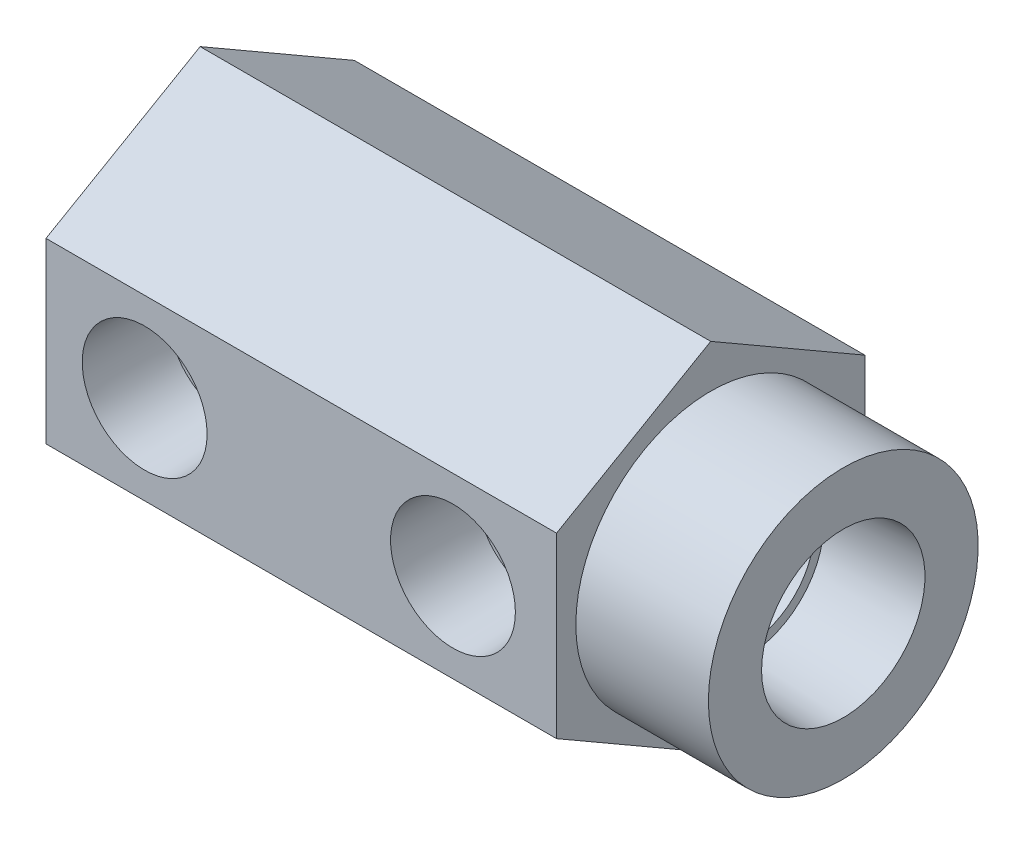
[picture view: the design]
ISO-10303-21;
HEADER;
FILE_DESCRIPTION(('STEP AP214'),'2;1');
FILE_NAME('part.step','',(''),(''),'','','');
FILE_SCHEMA(('AUTOMOTIVE_DESIGN { 1 0 10303 214 1 1 1 1 }'));
ENDSEC;
DATA;
#1=APPLICATION_CONTEXT('core data for automotive mechanical design processes');
#2=APPLICATION_PROTOCOL_DEFINITION('international standard','automotive_design',2000,#1);
#3=PRODUCT_CONTEXT('',#1,'mechanical');
#4=PRODUCT('Part','Part','',(#3));
#5=PRODUCT_RELATED_PRODUCT_CATEGORY('part','',(#4));
#6=PRODUCT_DEFINITION_FORMATION('','',#4);
#7=PRODUCT_DEFINITION_CONTEXT('part definition',#1,'design');
#8=PRODUCT_DEFINITION('design','',#6,#7);
#9=PRODUCT_DEFINITION_SHAPE('','',#8);
#10=(LENGTH_UNIT() NAMED_UNIT(*) SI_UNIT(.MILLI.,.METRE.));
#11=(NAMED_UNIT(*) PLANE_ANGLE_UNIT() SI_UNIT($,.RADIAN.));
#12=(NAMED_UNIT(*) SI_UNIT($,.STERADIAN.) SOLID_ANGLE_UNIT());
#13=UNCERTAINTY_MEASURE_WITH_UNIT(LENGTH_MEASURE(1.E-05),#10,'distance_accuracy_value','');
#14=(GEOMETRIC_REPRESENTATION_CONTEXT(3) GLOBAL_UNCERTAINTY_ASSIGNED_CONTEXT((#13)) GLOBAL_UNIT_ASSIGNED_CONTEXT((#10,
#11,#12)) REPRESENTATION_CONTEXT('',''));
#15=CARTESIAN_POINT('',(0.,0.,0.));
#16=DIRECTION('',(0.,0.,1.));
#17=DIRECTION('',(1.,0.,0.));
#18=AXIS2_PLACEMENT_3D('',#15,#16,#17);
#19=CARTESIAN_POINT('',(52.9844,0.,0.));
#20=DIRECTION('',(1.,0.,0.));
#21=DIRECTION('',(0.,0.,-1.));
#22=AXIS2_PLACEMENT_3D('',#19,#20,#21);
#23=CYLINDRICAL_SURFACE('',#22,3.96875);
#24=CARTESIAN_POINT('',(16.4084,0.,0.));
#25=DIRECTION('',(1.,0.,0.));
#26=DIRECTION('',(0.,0.,-1.));
#27=AXIS2_PLACEMENT_3D('',#24,#25,#26);
#28=CIRCLE('',#27,3.96874999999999);
#29=CARTESIAN_POINT('',(16.4084,0.,-3.96874999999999));
#30=VERTEX_POINT('',#29);
#31=EDGE_CURVE('E159',#30,#30,#28,.T.);
#32=ORIENTED_EDGE('',*,*,#31,.F.);
#33=EDGE_LOOP('',(#32));
#34=FACE_BOUND('',#33,.T.);
#35=CARTESIAN_POINT('',(27.5844,0.,0.));
#36=DIRECTION('',(1.,0.,0.));
#37=DIRECTION('',(0.,0.,-1.));
#38=AXIS2_PLACEMENT_3D('',#35,#36,#37);
#39=CIRCLE('',#38,3.96875);
#40=CARTESIAN_POINT('',(27.5844,0.,-3.96875));
#41=VERTEX_POINT('',#40);
#42=EDGE_CURVE('E38',#41,#41,#39,.F.);
#43=ORIENTED_EDGE('',*,*,#42,.F.);
#44=EDGE_LOOP('',(#43));
#45=FACE_BOUND('',#44,.T.);
#46=ADVANCED_FACE('F34',(#34,#45),#23,.F.);
#47=CARTESIAN_POINT('',(33.528,0.,12.7));
#48=DIRECTION('',(0.,0.,1.));
#49=DIRECTION('',(1.,0.,0.));
#50=AXIS2_PLACEMENT_3D('',#47,#48,#49);
#51=CYLINDRICAL_SURFACE('',#50,4.2164);
#52=CARTESIAN_POINT('',(33.528,0.,5.77596));
#53=DIRECTION('',(0.,0.,1.));
#54=DIRECTION('',(1.,0.,0.));
#55=AXIS2_PLACEMENT_3D('',#52,#53,#54);
#56=CIRCLE('',#55,4.2164);
#57=CARTESIAN_POINT('',(37.7444,0.,5.77596));
#58=VERTEX_POINT('',#57);
#59=EDGE_CURVE('E318',#58,#58,#56,.T.);
#60=ORIENTED_EDGE('',*,*,#59,.T.);
#61=EDGE_LOOP('',(#60));
#62=FACE_BOUND('',#61,.T.);
#63=CARTESIAN_POINT('',(37.7444,0.,5.54990000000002));
#64=CARTESIAN_POINT('',(37.7443993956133,0.102666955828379,5.54989942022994));
#65=CARTESIAN_POINT('',(37.7406438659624,0.205343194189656,5.54704470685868));
#66=CARTESIAN_POINT('',(37.7256842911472,0.409877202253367,5.53569249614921));
#67=CARTESIAN_POINT('',(37.7144766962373,0.511734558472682,5.52719230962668));
#68=CARTESIAN_POINT('',(37.6847756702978,0.713930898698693,5.50472974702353));
#69=CARTESIAN_POINT('',(37.6662712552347,0.814267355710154,5.49075913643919));
#70=CARTESIAN_POINT('',(37.6222775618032,1.01254840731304,5.45767930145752));
#71=CARTESIAN_POINT('',(37.5967851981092,1.11049192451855,5.43856780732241));
#72=CARTESIAN_POINT('',(37.5107274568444,1.398497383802,5.37438339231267));
#73=CARTESIAN_POINT('',(37.440361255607,1.58418379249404,5.32229076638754));
#74=CARTESIAN_POINT('',(37.276841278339,1.93974746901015,5.2032718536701));
#75=CARTESIAN_POINT('',(37.1836912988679,2.10962736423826,5.1363480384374));
#76=CARTESIAN_POINT('',(36.9680945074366,2.44693461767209,4.98509307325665));
#77=CARTESIAN_POINT('',(36.8437265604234,2.61265837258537,4.89972096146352));
#78=CARTESIAN_POINT('',(36.5743774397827,2.92229860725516,4.72159970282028));
#79=CARTESIAN_POINT('',(36.4293655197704,3.06618188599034,4.62883964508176));
#80=CARTESIAN_POINT('',(36.1818679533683,3.27873581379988,4.47894046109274));
#81=CARTESIAN_POINT('',(36.0852396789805,3.35465016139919,4.4222195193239));
#82=CARTESIAN_POINT('',(35.8853172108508,3.49803153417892,4.30969399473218));
#83=CARTESIAN_POINT('',(35.7820209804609,3.56549595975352,4.25388969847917));
#84=CARTESIAN_POINT('',(35.5689644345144,3.69158445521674,4.14494021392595));
#85=CARTESIAN_POINT('',(35.459210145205,3.75021659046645,4.091792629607));
#86=CARTESIAN_POINT('',(35.2332788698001,3.85820397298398,3.99013143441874));
#87=CARTESIAN_POINT('',(35.1171056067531,3.90756452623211,3.94161518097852));
#88=CARTESIAN_POINT('',(34.8423535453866,4.00972513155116,3.83800214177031));
#89=CARTESIAN_POINT('',(34.6815147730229,4.05910874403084,3.78530268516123));
#90=CARTESIAN_POINT('',(34.4334747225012,4.11890503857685,3.71979682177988));
#91=CARTESIAN_POINT('',(34.3497154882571,4.13645117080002,3.70022626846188));
#92=CARTESIAN_POINT('',(34.1802742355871,4.16652842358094,3.66632583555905));
#93=CARTESIAN_POINT('',(34.0945932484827,4.17906216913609,3.65199321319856));
#94=CARTESIAN_POINT('',(33.9209530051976,4.19896788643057,3.62908998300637));
#95=CARTESIAN_POINT('',(33.8329793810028,4.2062854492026,3.62058014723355));
#96=CARTESIAN_POINT('',(33.6563570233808,4.2153732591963,3.60999553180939));
#97=CARTESIAN_POINT('',(33.5677083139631,4.21714370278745,3.60792052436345));
#98=CARTESIAN_POINT('',(33.3905433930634,4.21508975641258,3.61032018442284));
#99=CARTESIAN_POINT('',(33.3020272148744,4.21126414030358,3.61479628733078));
#100=CARTESIAN_POINT('',(33.1259748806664,4.1981195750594,3.63005192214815));
#101=CARTESIAN_POINT('',(33.038438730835,4.18880059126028,3.64083149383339));
#102=CARTESIAN_POINT('',(32.7985166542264,4.15568903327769,3.67868158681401));
#103=CARTESIAN_POINT('',(32.6478348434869,4.1262776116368,3.71190594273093));
#104=CARTESIAN_POINT('',(32.3540921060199,4.05253036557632,3.79227022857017));
#105=CARTESIAN_POINT('',(32.211039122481,4.00817932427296,3.83942434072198));
#106=CARTESIAN_POINT('',(31.9583831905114,3.91523448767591,3.93394303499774));
#107=CARTESIAN_POINT('',(31.847374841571,3.86881960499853,3.97976043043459));
#108=CARTESIAN_POINT('',(31.6311954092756,3.7675481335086,4.07576238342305));
#109=CARTESIAN_POINT('',(31.5260274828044,3.71268703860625,4.12594926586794));
#110=CARTESIAN_POINT('',(31.3214051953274,3.5948485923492,4.22901830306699));
#111=CARTESIAN_POINT('',(31.2219633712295,3.53185434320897,4.28190592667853));
#112=CARTESIAN_POINT('',(31.0290973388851,3.39812936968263,4.38878526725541));
#113=CARTESIAN_POINT('',(30.9356721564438,3.32739990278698,4.44277680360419));
#114=CARTESIAN_POINT('',(30.7523590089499,3.17621734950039,4.55214005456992));
#115=CARTESIAN_POINT('',(30.662649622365,3.09554338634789,4.60750688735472));
#116=CARTESIAN_POINT('',(30.4900225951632,2.92631985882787,4.7168012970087));
#117=CARTESIAN_POINT('',(30.4071076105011,2.83776724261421,4.77072830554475));
#118=CARTESIAN_POINT('',(30.1695373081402,2.56081846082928,4.92833957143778));
#119=CARTESIAN_POINT('',(30.0255232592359,2.36069403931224,5.02818332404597));
#120=CARTESIAN_POINT('',(29.79622654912,1.97290355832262,5.19079382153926));
#121=CARTESIAN_POINT('',(29.704976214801,1.79022627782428,5.25699864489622));
#122=CARTESIAN_POINT('',(29.5877201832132,1.50428240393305,5.34307696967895));
#123=CARTESIAN_POINT('',(29.5518975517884,1.40695118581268,5.36957042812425));
#124=CARTESIAN_POINT('',(29.487255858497,1.20882529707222,5.41761054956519));
#125=CARTESIAN_POINT('',(29.4584337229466,1.10803216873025,5.43915938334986));
#126=CARTESIAN_POINT('',(29.4080388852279,0.902877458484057,5.47696644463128));
#127=CARTESIAN_POINT('',(29.3865198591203,0.798495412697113,5.49318547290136));
#128=CARTESIAN_POINT('',(29.3513945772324,0.587711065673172,5.5197156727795));
#129=CARTESIAN_POINT('',(29.3377846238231,0.481309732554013,5.53002960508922));
#130=CARTESIAN_POINT('',(29.3187165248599,0.267379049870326,5.54449183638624));
#131=CARTESIAN_POINT('',(29.3132569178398,0.159849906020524,5.54864124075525));
#132=CARTESIAN_POINT('',(29.31059043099,-0.0553630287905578,5.55066695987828));
#133=CARTESIAN_POINT('',(29.3133828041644,-0.163046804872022,5.54854384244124));
#134=CARTESIAN_POINT('',(29.3264157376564,-0.365919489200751,5.53865106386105));
#135=CARTESIAN_POINT('',(29.3358141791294,-0.461194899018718,5.5315198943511));
#136=CARTESIAN_POINT('',(29.3609746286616,-0.65042738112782,5.51247648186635));
#137=CARTESIAN_POINT('',(29.3767386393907,-0.744384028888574,5.50056273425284));
#138=CARTESIAN_POINT('',(29.4332697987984,-1.02327908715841,5.4579792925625));
#139=CARTESIAN_POINT('',(29.4832871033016,-1.20540685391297,5.42045882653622));
#140=CARTESIAN_POINT('',(29.6070842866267,-1.56242729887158,5.32871242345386));
#141=CARTESIAN_POINT('',(29.6814572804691,-1.73700152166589,5.27407116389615));
#142=CARTESIAN_POINT('',(29.8505450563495,-2.07109183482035,5.15204916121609));
#143=CARTESIAN_POINT('',(29.9452628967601,-2.23060565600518,5.08466650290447));
#144=CARTESIAN_POINT('',(30.1694079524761,-2.55802504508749,4.92909083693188));
#145=CARTESIAN_POINT('',(30.3019810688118,-2.72300325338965,4.83929765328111));
#146=CARTESIAN_POINT('',(30.5883037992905,-3.02991540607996,4.65330404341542));
#147=CARTESIAN_POINT('',(30.7420960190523,-3.17180170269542,4.55709093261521));
#148=CARTESIAN_POINT('',(31.0034639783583,-3.3794070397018,4.40345363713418));
#149=CARTESIAN_POINT('',(31.1049126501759,-3.45288781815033,4.34591141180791));
#150=CARTESIAN_POINT('',(31.314685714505,-3.5909673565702,4.23253042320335));
#151=CARTESIAN_POINT('',(31.4230125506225,-3.65556293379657,4.17669227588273));
#152=CARTESIAN_POINT('',(31.6462598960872,-3.7753266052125,4.06875742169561));
#153=CARTESIAN_POINT('',(31.7611678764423,-3.83051186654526,4.01665400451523));
#154=CARTESIAN_POINT('',(31.9975785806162,-3.93094643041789,3.91841531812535));
#155=CARTESIAN_POINT('',(32.1190762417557,-3.97620322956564,3.87227555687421));
#156=CARTESIAN_POINT('',(32.3974988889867,-4.06520982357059,3.77896121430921));
#157=CARTESIAN_POINT('',(32.5561211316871,-4.10619306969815,3.7340128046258));
#158=CARTESIAN_POINT('',(32.7996105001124,-4.15383268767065,3.68070998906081));
#159=CARTESIAN_POINT('',(32.8816471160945,-4.16740255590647,3.66530086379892));
#160=CARTESIAN_POINT('',(33.0471718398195,-4.18972486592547,3.63976459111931));
#161=CARTESIAN_POINT('',(33.1306592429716,-4.19847958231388,3.62963494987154));
#162=CARTESIAN_POINT('',(33.2991320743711,-4.21103758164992,3.61505835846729));
#163=CARTESIAN_POINT('',(33.3841240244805,-4.21480358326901,3.6106542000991));
#164=CARTESIAN_POINT('',(33.5542775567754,-4.21717640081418,3.60788260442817));
#165=CARTESIAN_POINT('',(33.639439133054,-4.21578339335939,3.60951496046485));
#166=CARTESIAN_POINT('',(33.8092521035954,-4.20786839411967,3.61873867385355));
#167=CARTESIAN_POINT('',(33.8939031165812,-4.20134295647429,3.62633403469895));
#168=CARTESIAN_POINT('',(34.0620056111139,-4.18330254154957,3.64713005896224));
#169=CARTESIAN_POINT('',(34.1454564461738,-4.17178497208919,3.66033363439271));
#170=CARTESIAN_POINT('',(34.3240534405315,-4.1417155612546,3.69434379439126));
#171=CARTESIAN_POINT('',(34.4188890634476,-4.12232321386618,3.71603879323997));
#172=CARTESIAN_POINT('',(34.6056232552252,-4.07749843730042,3.7651699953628));
#173=CARTESIAN_POINT('',(34.697519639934,-4.05206162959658,3.79261035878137));
#174=CARTESIAN_POINT('',(34.9685718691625,-3.96719813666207,3.88193715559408));
#175=CARTESIAN_POINT('',(35.1428493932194,-3.89926066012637,3.95077814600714));
#176=CARTESIAN_POINT('',(35.426054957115,-3.76720881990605,4.07616702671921));
#177=CARTESIAN_POINT('',(35.5387046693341,-3.70824622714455,4.13006200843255));
#178=CARTESIAN_POINT('',(35.7572672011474,-3.5811127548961,4.24076863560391));
#179=CARTESIAN_POINT('',(35.8631775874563,-3.51293857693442,4.29758132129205));
#180=CARTESIAN_POINT('',(36.0681950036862,-3.36767607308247,4.41233843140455));
#181=CARTESIAN_POINT('',(36.167295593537,-3.29057948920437,4.47028386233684));
#182=CARTESIAN_POINT('',(36.3583871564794,-3.12772920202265,4.58570164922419));
#183=CARTESIAN_POINT('',(36.450379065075,-3.04197664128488,4.64317406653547));
#184=CARTESIAN_POINT('',(36.6281804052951,-2.86064113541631,4.75707411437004));
#185=CARTESIAN_POINT('',(36.7138800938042,-2.76493305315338,4.81347428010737));
#186=CARTESIAN_POINT('',(36.8770160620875,-2.56491197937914,4.9229681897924));
#187=CARTESIAN_POINT('',(36.954451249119,-2.46059785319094,4.9760614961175));
#188=CARTESIAN_POINT('',(37.100127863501,-2.24386878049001,5.07747289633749));
#189=CARTESIAN_POINT('',(37.1683863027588,-2.13146943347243,5.12579978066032));
#190=CARTESIAN_POINT('',(37.29491910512,-1.89890802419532,5.21642520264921));
#191=CARTESIAN_POINT('',(37.3531981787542,-1.77874966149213,5.25872658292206));
#192=CARTESIAN_POINT('',(37.4439058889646,-1.56622364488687,5.32513054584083));
#193=CARTESIAN_POINT('',(37.4789964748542,-1.47553606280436,5.35100662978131));
#194=CARTESIAN_POINT('',(37.5430944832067,-1.29096184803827,5.39850728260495));
#195=CARTESIAN_POINT('',(37.5721033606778,-1.19707598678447,5.420132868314));
#196=CARTESIAN_POINT('',(37.6236159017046,-1.00680382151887,5.4586756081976));
#197=CARTESIAN_POINT('',(37.6461329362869,-0.910423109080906,5.47560243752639));
#198=CARTESIAN_POINT('',(37.6844114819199,-0.715624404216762,5.50444899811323));
#199=CARTESIAN_POINT('',(37.700175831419,-0.61720728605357,5.5163708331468));
#200=CARTESIAN_POINT('',(37.7230526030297,-0.432452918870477,5.53369497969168));
#201=CARTESIAN_POINT('',(37.7310480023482,-0.34628607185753,5.53976185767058));
#202=CARTESIAN_POINT('',(37.7417225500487,-0.173415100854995,5.54786506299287));
#203=CARTESIAN_POINT('',(37.7444005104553,-0.0867108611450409,5.54990048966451));
#204=CARTESIAN_POINT('',(37.7444,0.,5.54990000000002));
#205=B_SPLINE_CURVE_WITH_KNOTS('',3,(#63,#64,#65,#66,#67,#68,#69,#70,#71,#72,#73,#74,#75,#76,
#77,#78,#79,#80,#81,#82,#83,#84,#85,#86,#87,#88,#89,#90,#91,#92,#93,#94,#95,#96,#97,#98,#99,
#100,#101,#102,#103,#104,#105,#106,#107,#108,#109,#110,#111,#112,#113,#114,#115,#116,#117,#118,
#119,#120,#121,#122,#123,#124,#125,#126,#127,#128,#129,#130,#131,#132,#133,#134,#135,#136,#137,
#138,#139,#140,#141,#142,#143,#144,#145,#146,#147,#148,#149,#150,#151,#152,#153,#154,#155,#156,
#157,#158,#159,#160,#161,#162,#163,#164,#165,#166,#167,#168,#169,#170,#171,#172,#173,#174,#175,
#176,#177,#178,#179,#180,#181,#182,#183,#184,#185,#186,#187,#188,#189,#190,#191,#192,#193,#194,
#195,#196,#197,#198,#199,#200,#201,#202,#203,#204),.UNSPECIFIED.,.T.,.F.,(4,2,2,2,2,2,2,2,2,2,2,
2,2,2,2,2,2,2,2,2,2,2,2,2,2,2,2,2,2,2,2,2,2,2,2,2,2,2,2,2,2,2,2,2,2,2,2,2,2,2,2,2,2,2,2,2,2,2,2,
2,2,2,2,2,2,2,2,2,2,2,4),(0.,0.307909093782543,0.615964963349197,0.924486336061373,
1.23314414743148,1.84608968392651,2.45893315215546,3.12888302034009,3.79984133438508,
4.20549409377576,4.61127134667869,5.01667578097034,5.42184749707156,5.94866107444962,
6.21175949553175,6.47471995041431,6.74038467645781,7.00603999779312,7.2717535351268,
7.53746874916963,8.00678580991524,8.47658235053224,8.86232249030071,9.24826914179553,
9.63503095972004,10.0217299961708,10.4195319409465,10.817488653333,11.6111347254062,
12.2523588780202,12.5731486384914,12.8937972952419,13.2167540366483,13.5395596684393,
13.8623074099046,14.1850259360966,14.4726847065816,14.7604340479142,15.3354443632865,
15.925652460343,16.5159493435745,17.2032337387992,17.891918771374,18.3050679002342,
18.7183646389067,19.1308991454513,19.543121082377,20.0506303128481,20.3040712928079,
20.5573924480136,20.8125962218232,21.0677912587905,21.323157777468,21.5786570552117,
21.8757972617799,22.1731533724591,22.7686074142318,23.1824806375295,23.5965024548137,
24.0109105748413,24.4252640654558,24.8456610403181,25.266113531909,25.6857755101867,
26.1052388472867,26.4068178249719,26.7083245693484,27.0092058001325,27.3099604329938,
27.5699574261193,27.8300124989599),.UNSPECIFIED.);
#206=CARTESIAN_POINT('',(37.7444,0.,5.54990000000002));
#207=VERTEX_POINT('',#206);
#208=EDGE_CURVE('E372',#207,#207,#205,.T.);
#209=ORIENTED_EDGE('',*,*,#208,.F.);
#210=EDGE_LOOP('',(#209));
#211=FACE_BOUND('',#210,.T.);
#212=ADVANCED_FACE('F234',(#62,#211),#51,.F.);
#213=CARTESIAN_POINT('',(52.9844,0.,0.));
#214=DIRECTION('',(1.,0.,0.));
#215=DIRECTION('',(0.,0.,-1.));
#216=AXIS2_PLACEMENT_3D('',#213,#214,#215);
#217=PLANE('',#216);
#218=CARTESIAN_POINT('',(52.9844,0.,0.));
#219=DIRECTION('',(1.,0.,0.));
#220=DIRECTION('',(0.,0.,-1.));
#221=AXIS2_PLACEMENT_3D('',#218,#219,#220);
#222=CIRCLE('',#221,11.1125);
#223=CARTESIAN_POINT('',(52.9844,0.,11.1125));
#224=VERTEX_POINT('',#223);
#225=EDGE_CURVE('E264',#224,#224,#222,.T.);
#226=ORIENTED_EDGE('',*,*,#225,.T.);
#227=EDGE_LOOP('',(#226));
#228=FACE_BOUND('',#227,.T.);
#229=CARTESIAN_POINT('',(52.9844,0.,0.));
#230=DIRECTION('',(-1.,0.,0.));
#231=DIRECTION('',(0.,0.,1.));
#232=AXIS2_PLACEMENT_3D('',#229,#230,#231);
#233=CIRCLE('',#232,6.73100000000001);
#234=CARTESIAN_POINT('',(52.9844,0.,6.73100000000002));
#235=VERTEX_POINT('',#234);
#236=EDGE_CURVE('E388',#235,#235,#233,.T.);
#237=ORIENTED_EDGE('',*,*,#236,.T.);
#238=EDGE_LOOP('',(#237));
#239=FACE_BOUND('',#238,.T.);
#240=ADVANCED_FACE('F530',(#228,#239),#217,.T.);
#241=CARTESIAN_POINT('',(52.9844,0.,0.));
#242=DIRECTION('',(1.,0.,0.));
#243=DIRECTION('',(0.,0.,-1.));
#244=AXIS2_PLACEMENT_3D('',#241,#242,#243);
#245=CYLINDRICAL_SURFACE('',#244,2.77812499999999);
#246=CARTESIAN_POINT('',(11.3005129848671,0.,0.));
#247=DIRECTION('',(1.,0.,0.));
#248=DIRECTION('',(0.,0.,-1.));
#249=AXIS2_PLACEMENT_3D('',#246,#247,#248);
#250=CIRCLE('',#249,2.77812499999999);
#251=CARTESIAN_POINT('',(11.3005129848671,-2.77726309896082,-0.0691967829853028));
#252=VERTEX_POINT('',#251);
#253=CARTESIAN_POINT('',(11.3005129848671,-2.77726309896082,0.0691967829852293));
#254=VERTEX_POINT('',#253);
#255=EDGE_CURVE('E156',#252,#254,#250,.F.);
#256=ORIENTED_EDGE('',*,*,#255,.F.);
#257=CARTESIAN_POINT('',(11.3005129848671,-2.77726309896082,-0.0691967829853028));
#258=CARTESIAN_POINT('',(11.3000098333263,-2.7778376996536,-0.0461311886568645));
#259=CARTESIAN_POINT('',(11.2997582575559,-2.77812499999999,-0.0230655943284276));
#260=CARTESIAN_POINT('',(11.2997582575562,-2.77812499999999,0.0230655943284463));
#261=CARTESIAN_POINT('',(11.3000098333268,-2.7778376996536,0.0461311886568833));
#262=CARTESIAN_POINT('',(11.3005129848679,-2.77726309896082,0.0691967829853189));
#263=B_SPLINE_CURVE_WITH_KNOTS('',3,(#257,#258,#259,#260,#261,#262),.UNSPECIFIED.,.F.,.F.,(4,2,
4),(0.,0.0692062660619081,0.138412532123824),.UNSPECIFIED.);
#264=EDGE_CURVE('E195',#252,#254,#263,.T.);
#265=ORIENTED_EDGE('',*,*,#264,.T.);
#266=EDGE_LOOP('',(#256,#265));
#267=FACE_BOUND('',#266,.T.);
#268=ADVANCED_FACE('F228',(#267),#245,.F.);
#269=CARTESIAN_POINT('',(11.70686,0.,0.));
#270=DIRECTION('',(1.,0.,0.));
#271=DIRECTION('',(0.,0.,-1.));
#272=AXIS2_PLACEMENT_3D('',#269,#270,#271);
#273=CONICAL_SURFACE('',#272,3.45439999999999,1.02974425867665);
#274=CARTESIAN_POINT('',(11.70686,0.,0.));
#275=DIRECTION('',(1.,0.,0.));
#276=DIRECTION('',(0.,0.,-1.));
#277=AXIS2_PLACEMENT_3D('',#274,#275,#276);
#278=CIRCLE('',#277,3.45439999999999);
#279=CARTESIAN_POINT('',(11.70686,2.22930259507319,-2.63876662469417));
#280=VERTEX_POINT('',#279);
#281=CARTESIAN_POINT('',(11.70686,2.22930259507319,2.63876662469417));
#282=VERTEX_POINT('',#281);
#283=EDGE_CURVE('E257',#280,#282,#278,.T.);
#284=ORIENTED_EDGE('',*,*,#283,.T.);
#285=CARTESIAN_POINT('',(11.7476947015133,2.16236889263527,2.78050053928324));
#286=CARTESIAN_POINT('',(11.7271753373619,2.19671154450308,2.71052294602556));
#287=CARTESIAN_POINT('',(11.7069334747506,2.22949125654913,2.63971409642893));
#288=CARTESIAN_POINT('',(11.667206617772,2.29203475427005,2.49657500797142));
#289=CARTESIAN_POINT('',(11.6477215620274,2.32179878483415,2.42424489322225));
#290=CARTESIAN_POINT('',(11.5906937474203,2.40674864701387,2.20514532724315));
#291=CARTESIAN_POINT('',(11.5545845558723,2.45758211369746,2.0562875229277));
#292=CARTESIAN_POINT('',(11.4879159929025,2.54796742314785,1.75435447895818));
#293=CARTESIAN_POINT('',(11.4573449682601,2.58754305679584,1.60128889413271));
#294=CARTESIAN_POINT('',(11.4032660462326,2.65566485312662,1.29149058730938));
#295=CARTESIAN_POINT('',(11.3797575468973,2.68421195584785,1.13475817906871));
#296=CARTESIAN_POINT('',(11.3411209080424,2.7303482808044,0.817376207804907));
#297=CARTESIAN_POINT('',(11.3260598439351,2.747849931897,0.656705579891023));
#298=CARTESIAN_POINT('',(11.3057062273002,2.77136403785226,0.333913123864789));
#299=CARTESIAN_POINT('',(11.300412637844,2.77737771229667,0.171791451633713));
#300=CARTESIAN_POINT('',(11.3000110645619,2.77783639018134,-0.152482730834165));
#301=CARTESIAN_POINT('',(11.3049031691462,2.77228129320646,-0.314635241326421));
#302=CARTESIAN_POINT('',(11.3244850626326,2.74967834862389,-0.637543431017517));
#303=CARTESIAN_POINT('',(11.3391758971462,2.73262927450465,-0.79829895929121));
#304=CARTESIAN_POINT('',(11.3773154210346,2.68716479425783,-1.11745832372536));
#305=CARTESIAN_POINT('',(11.4007817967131,2.65872642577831,-1.27585673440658));
#306=CARTESIAN_POINT('',(11.454965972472,2.59060164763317,-1.58894463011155));
#307=CARTESIAN_POINT('',(11.4856845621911,2.55091401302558,-1.74363370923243));
#308=CARTESIAN_POINT('',(11.5527968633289,2.46008005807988,-2.04877208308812));
#309=CARTESIAN_POINT('',(11.5892035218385,2.40890747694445,-2.19921075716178));
#310=CARTESIAN_POINT('',(11.6467473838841,2.32327906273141,-2.42060205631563));
#311=CARTESIAN_POINT('',(11.6664157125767,2.29326115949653,-2.49368153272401));
#312=CARTESIAN_POINT('',(11.7065265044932,2.23015008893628,-2.63829019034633));
#313=CARTESIAN_POINT('',(11.7269690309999,2.19705666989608,-2.70981924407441));
#314=CARTESIAN_POINT('',(11.7476947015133,2.16236889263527,-2.78050053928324));
#315=B_SPLINE_CURVE_WITH_KNOTS('',3,(#285,#286,#287,#288,#289,#290,#291,#292,#293,#294,#295,
#296,#297,#298,#299,#300,#301,#302,#303,#304,#305,#306,#307,#308,#309,#310,#311,#312,#313,#314),
.UNSPECIFIED.,.F.,.F.,(4,2,2,2,2,2,2,2,2,2,2,2,2,2,4),(0.,0.241771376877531,0.483523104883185,
0.967098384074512,1.44964401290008,1.93214850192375,2.41843187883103,2.90466362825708,
3.39089959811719,3.87718746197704,4.36446072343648,4.85178706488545,5.34023926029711,
5.58442058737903,5.82862191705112),.UNSPECIFIED.);
#316=CARTESIAN_POINT('',(11.3005129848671,2.77726309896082,0.0691967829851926));
#317=VERTEX_POINT('',#316);
#318=EDGE_CURVE('E11',#282,#317,#315,.T.);
#319=ORIENTED_EDGE('',*,*,#318,.T.);
#320=CARTESIAN_POINT('',(11.3005129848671,2.77726309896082,-0.0691967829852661));
#321=VERTEX_POINT('',#320);
#322=EDGE_CURVE('E160',#317,#321,#250,.F.);
#323=ORIENTED_EDGE('',*,*,#322,.T.);
#324=EDGE_CURVE('E43',#321,#280,#315,.T.);
#325=ORIENTED_EDGE('',*,*,#324,.T.);
#326=EDGE_LOOP('',(#284,#319,#323,#325));
#327=FACE_BOUND('',#326,.T.);
#328=ADVANCED_FACE('F246',(#327),#273,.F.);
#329=CARTESIAN_POINT('',(11.70686,-2.22930259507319,2.63876662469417));
#330=VERTEX_POINT('',#329);
#331=CARTESIAN_POINT('',(11.70686,-2.22930259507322,-2.63876662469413));
#332=VERTEX_POINT('',#331);
#333=EDGE_CURVE('E252',#330,#332,#278,.T.);
#334=ORIENTED_EDGE('',*,*,#333,.T.);
#335=CARTESIAN_POINT('',(11.7476947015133,-2.16236889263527,-2.78050053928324));
#336=CARTESIAN_POINT('',(11.7271753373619,-2.19671154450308,-2.71052294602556));
#337=CARTESIAN_POINT('',(11.7069334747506,-2.22949125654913,-2.63971409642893));
#338=CARTESIAN_POINT('',(11.667206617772,-2.29203475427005,-2.49657500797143));
#339=CARTESIAN_POINT('',(11.6477215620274,-2.32179878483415,-2.42424489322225));
#340=CARTESIAN_POINT('',(11.5906937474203,-2.40674864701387,-2.20514532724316));
#341=CARTESIAN_POINT('',(11.5545845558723,-2.45758211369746,-2.0562875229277));
#342=CARTESIAN_POINT('',(11.4879159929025,-2.54796742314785,-1.75435447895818));
#343=CARTESIAN_POINT('',(11.4573449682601,-2.58754305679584,-1.60128889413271));
#344=CARTESIAN_POINT('',(11.4032660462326,-2.65566485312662,-1.29149058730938));
#345=CARTESIAN_POINT('',(11.3797575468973,-2.68421195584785,-1.13475817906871));
#346=CARTESIAN_POINT('',(11.3411209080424,-2.7303482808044,-0.817376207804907));
#347=CARTESIAN_POINT('',(11.3260598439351,-2.747849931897,-0.656705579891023));
#348=CARTESIAN_POINT('',(11.3057062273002,-2.77136403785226,-0.333913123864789));
#349=CARTESIAN_POINT('',(11.300412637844,-2.77737771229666,-0.171791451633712));
#350=CARTESIAN_POINT('',(11.3000110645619,-2.77783639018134,0.152482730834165));
#351=CARTESIAN_POINT('',(11.3049031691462,-2.77228129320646,0.314635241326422));
#352=CARTESIAN_POINT('',(11.3244850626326,-2.74967834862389,0.637543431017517));
#353=CARTESIAN_POINT('',(11.3391758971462,-2.73262927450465,0.79829895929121));
#354=CARTESIAN_POINT('',(11.3773154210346,-2.68716479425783,1.11745832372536));
#355=CARTESIAN_POINT('',(11.4007817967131,-2.65872642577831,1.27585673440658));
#356=CARTESIAN_POINT('',(11.454965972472,-2.59060164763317,1.58894463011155));
#357=CARTESIAN_POINT('',(11.4856845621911,-2.55091401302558,1.74363370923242));
#358=CARTESIAN_POINT('',(11.5527968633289,-2.46008005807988,2.04877208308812));
#359=CARTESIAN_POINT('',(11.5892035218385,-2.40890747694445,2.19921075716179));
#360=CARTESIAN_POINT('',(11.6467473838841,-2.32327906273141,2.42060205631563));
#361=CARTESIAN_POINT('',(11.6664157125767,-2.29326115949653,2.49368153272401));
#362=CARTESIAN_POINT('',(11.7065265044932,-2.23015008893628,2.63829019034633));
#363=CARTESIAN_POINT('',(11.7269690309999,-2.19705666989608,2.70981924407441));
#364=CARTESIAN_POINT('',(11.7476947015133,-2.16236889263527,2.78050053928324));
#365=B_SPLINE_CURVE_WITH_KNOTS('',3,(#335,#336,#337,#338,#339,#340,#341,#342,#343,#344,#345,
#346,#347,#348,#349,#350,#351,#352,#353,#354,#355,#356,#357,#358,#359,#360,#361,#362,#363,#364),
.UNSPECIFIED.,.F.,.F.,(4,2,2,2,2,2,2,2,2,2,2,2,2,2,4),(0.,0.241771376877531,0.483523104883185,
0.967098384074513,1.44964401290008,1.93214850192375,2.41843187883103,2.90466362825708,
3.39089959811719,3.87718746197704,4.36446072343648,4.85178706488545,5.34023926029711,
5.58442058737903,5.82862191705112),.UNSPECIFIED.);
#366=EDGE_CURVE('E167',#332,#252,#365,.T.);
#367=ORIENTED_EDGE('',*,*,#366,.T.);
#368=ORIENTED_EDGE('',*,*,#255,.T.);
#369=EDGE_CURVE('E155',#254,#330,#365,.T.);
#370=ORIENTED_EDGE('',*,*,#369,.T.);
#371=EDGE_LOOP('',(#334,#367,#368,#370));
#372=FACE_BOUND('',#371,.T.);
#373=ADVANCED_FACE('F173',(#372),#273,.F.);
#374=CARTESIAN_POINT('',(52.9844,0.,0.));
#375=DIRECTION('',(1.,0.,0.));
#376=DIRECTION('',(0.,0.,-1.));
#377=AXIS2_PLACEMENT_3D('',#374,#375,#376);
#378=CYLINDRICAL_SURFACE('',#377,3.45439999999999);
#379=ORIENTED_EDGE('',*,*,#333,.F.);
#380=CARTESIAN_POINT('',(11.70686,-2.22930259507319,2.63876662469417));
#381=CARTESIAN_POINT('',(11.7467414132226,-2.16526535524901,2.69284659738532));
#382=CARTESIAN_POINT('',(11.7856619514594,-2.09896011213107,2.74488489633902));
#383=CARTESIAN_POINT('',(11.8610723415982,-1.96172486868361,2.84460121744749));
#384=CARTESIAN_POINT('',(11.8975596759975,-1.89079022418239,2.89227474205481));
#385=CARTESIAN_POINT('',(12.0030465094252,-1.66994020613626,3.02889685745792));
#386=CARTESIAN_POINT('',(12.0674141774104,-1.51300299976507,3.11056973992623));
#387=CARTESIAN_POINT('',(12.1510306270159,-1.26529493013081,3.21559750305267));
#388=CARTESIAN_POINT('',(12.1768211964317,-1.18032276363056,3.2477832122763));
#389=CARTESIAN_POINT('',(12.2233944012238,-1.00688279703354,3.30566239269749));
#390=CARTESIAN_POINT('',(12.244180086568,-0.918417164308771,3.33135981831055));
#391=CARTESIAN_POINT('',(12.2801403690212,-0.738988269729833,3.37569055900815));
#392=CARTESIAN_POINT('',(12.2953360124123,-0.648035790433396,3.39435037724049));
#393=CARTESIAN_POINT('',(12.3198003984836,-0.464148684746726,3.42434180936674));
#394=CARTESIAN_POINT('',(12.3290703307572,-0.371214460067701,3.4356748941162));
#395=CARTESIAN_POINT('',(12.3405715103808,-0.197034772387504,3.44972786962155));
#396=CARTESIAN_POINT('',(12.3435879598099,-0.11591673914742,3.45340880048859));
#397=CARTESIAN_POINT('',(12.3449258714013,0.0464449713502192,3.45504190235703));
#398=CARTESIAN_POINT('',(12.3432458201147,0.127688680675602,3.4529922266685));
#399=CARTESIAN_POINT('',(12.3352233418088,0.289599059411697,3.44319428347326));
#400=CARTESIAN_POINT('',(12.3288810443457,0.370265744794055,3.43544617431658));
#401=CARTESIAN_POINT('',(12.3116838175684,0.530393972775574,3.41439539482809));
#402=CARTESIAN_POINT('',(12.3008271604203,0.609855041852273,3.40109059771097));
#403=CARTESIAN_POINT('',(12.2635759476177,0.834866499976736,3.35531661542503));
#404=CARTESIAN_POINT('',(12.2318582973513,0.978262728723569,3.31621805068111));
#405=CARTESIAN_POINT('',(12.1556088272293,1.25587210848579,3.22137777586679));
#406=CARTESIAN_POINT('',(12.1110596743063,1.39007253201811,3.1656135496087));
#407=CARTESIAN_POINT('',(12.0108978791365,1.64947218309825,3.03863421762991));
#408=CARTESIAN_POINT('',(11.9551189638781,1.77449212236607,2.96718523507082));
#409=CARTESIAN_POINT('',(11.8657306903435,1.95238147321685,2.8506309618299));
#410=CARTESIAN_POINT('',(11.8350456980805,2.00996969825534,2.81030250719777));
#411=CARTESIAN_POINT('',(11.7720769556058,2.12199249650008,2.72670082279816));
#412=CARTESIAN_POINT('',(11.7397941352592,2.17642886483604,2.68342930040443));
#413=CARTESIAN_POINT('',(11.70686,2.22930259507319,2.63876662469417));
#414=B_SPLINE_CURVE_WITH_KNOTS('',3,(#380,#381,#382,#383,#384,#385,#386,#387,#388,#389,#390,
#391,#392,#393,#394,#395,#396,#397,#398,#399,#400,#401,#402,#403,#404,#405,#406,#407,#408,#409,
#410,#411,#412,#413),.UNSPECIFIED.,.F.,.F.,(4,2,2,2,2,2,2,2,2,2,2,2,2,2,2,2,4),(0.,
0.278318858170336,0.556921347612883,1.1185834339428,1.40161006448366,1.6844637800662,
1.96624139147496,2.24796241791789,2.49140694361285,2.73492992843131,2.9784461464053,
3.22205565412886,3.67593136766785,4.13042308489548,4.5922178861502,4.82223300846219,
5.05211581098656),.UNSPECIFIED.);
#415=EDGE_CURVE('E51',#330,#282,#414,.T.);
#416=ORIENTED_EDGE('',*,*,#415,.T.);
#417=ORIENTED_EDGE('',*,*,#283,.F.);
#418=CARTESIAN_POINT('',(11.70686,2.22930259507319,-2.63876662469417));
#419=CARTESIAN_POINT('',(11.7467414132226,2.16526535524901,-2.69284659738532));
#420=CARTESIAN_POINT('',(11.7856619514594,2.09896011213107,-2.74488489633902));
#421=CARTESIAN_POINT('',(11.8610723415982,1.96172486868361,-2.84460121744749));
#422=CARTESIAN_POINT('',(11.8975596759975,1.89079022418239,-2.89227474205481));
#423=CARTESIAN_POINT('',(12.0030465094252,1.66994020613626,-3.02889685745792));
#424=CARTESIAN_POINT('',(12.0674141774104,1.51300299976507,-3.11056973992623));
#425=CARTESIAN_POINT('',(12.1510306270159,1.26529493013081,-3.21559750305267));
#426=CARTESIAN_POINT('',(12.1768211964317,1.18032276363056,-3.2477832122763));
#427=CARTESIAN_POINT('',(12.2233944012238,1.00688279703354,-3.30566239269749));
#428=CARTESIAN_POINT('',(12.244180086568,0.918417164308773,-3.33135981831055));
#429=CARTESIAN_POINT('',(12.2801403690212,0.738988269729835,-3.37569055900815));
#430=CARTESIAN_POINT('',(12.2953360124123,0.648035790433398,-3.39435037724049));
#431=CARTESIAN_POINT('',(12.3198003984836,0.464148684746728,-3.42434180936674));
#432=CARTESIAN_POINT('',(12.3290703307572,0.371214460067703,-3.4356748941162));
#433=CARTESIAN_POINT('',(12.3405715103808,0.197034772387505,-3.44972786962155));
#434=CARTESIAN_POINT('',(12.3435879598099,0.115916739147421,-3.45340880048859));
#435=CARTESIAN_POINT('',(12.3449258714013,-0.0464449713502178,-3.45504190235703));
#436=CARTESIAN_POINT('',(12.3432458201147,-0.1276886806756,-3.4529922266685));
#437=CARTESIAN_POINT('',(12.3352233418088,-0.289599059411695,-3.44319428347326));
#438=CARTESIAN_POINT('',(12.3288810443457,-0.370265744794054,-3.43544617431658));
#439=CARTESIAN_POINT('',(12.3116838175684,-0.530393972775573,-3.41439539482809));
#440=CARTESIAN_POINT('',(12.3008271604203,-0.609855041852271,-3.40109059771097));
#441=CARTESIAN_POINT('',(12.2635759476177,-0.834866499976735,-3.35531661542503));
#442=CARTESIAN_POINT('',(12.2318582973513,-0.978262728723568,-3.31621805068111));
#443=CARTESIAN_POINT('',(12.1556088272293,-1.25587210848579,-3.22137777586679));
#444=CARTESIAN_POINT('',(12.1110596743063,-1.39007253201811,-3.1656135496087));
#445=CARTESIAN_POINT('',(12.0108978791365,-1.64947218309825,-3.03863421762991));
#446=CARTESIAN_POINT('',(11.9551189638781,-1.77449212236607,-2.96718523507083));
#447=CARTESIAN_POINT('',(11.8657306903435,-1.95238147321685,-2.85063096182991));
#448=CARTESIAN_POINT('',(11.8350456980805,-2.00996969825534,-2.81030250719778));
#449=CARTESIAN_POINT('',(11.7720769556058,-2.12199249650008,-2.72670082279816));
#450=CARTESIAN_POINT('',(11.7397941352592,-2.17642886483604,-2.68342930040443));
#451=CARTESIAN_POINT('',(11.70686,-2.22930259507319,-2.63876662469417));
#452=B_SPLINE_CURVE_WITH_KNOTS('',3,(#418,#419,#420,#421,#422,#423,#424,#425,#426,#427,#428,
#429,#430,#431,#432,#433,#434,#435,#436,#437,#438,#439,#440,#441,#442,#443,#444,#445,#446,#447,
#448,#449,#450,#451),.UNSPECIFIED.,.F.,.F.,(4,2,2,2,2,2,2,2,2,2,2,2,2,2,2,2,4),(0.,
0.278318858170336,0.556921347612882,1.1185834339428,1.40161006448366,1.6844637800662,
1.96624139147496,2.24796241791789,2.49140694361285,2.73492992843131,2.9784461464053,
3.22205565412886,3.67593136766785,4.13042308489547,4.5922178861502,4.82223300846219,
5.05211581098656),.UNSPECIFIED.);
#453=EDGE_CURVE('E214',#280,#332,#452,.T.);
#454=ORIENTED_EDGE('',*,*,#453,.T.);
#455=EDGE_LOOP('',(#379,#416,#417,#454));
#456=FACE_BOUND('',#455,.T.);
#457=CARTESIAN_POINT('',(16.4084,0.,0.));
#458=DIRECTION('',(1.,0.,0.));
#459=DIRECTION('',(0.,0.,-1.));
#460=AXIS2_PLACEMENT_3D('',#457,#458,#459);
#461=CIRCLE('',#460,3.45439999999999);
#462=CARTESIAN_POINT('',(16.4084,0.,-3.45439999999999));
#463=VERTEX_POINT('',#462);
#464=EDGE_CURVE('E255',#463,#463,#461,.T.);
#465=ORIENTED_EDGE('',*,*,#464,.T.);
#466=EDGE_LOOP('',(#465));
#467=FACE_BOUND('',#466,.T.);
#468=ADVANCED_FACE('F237',(#456,#467),#378,.F.);
#469=CARTESIAN_POINT('',(16.4084,3.45439999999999,0.));
#470=DIRECTION('',(-1.,0.,0.));
#471=DIRECTION('',(0.,0.,1.));
#472=AXIS2_PLACEMENT_3D('',#469,#470,#471);
#473=PLANE('',#472);
#474=ORIENTED_EDGE('',*,*,#464,.F.);
#475=EDGE_LOOP('',(#474));
#476=FACE_BOUND('',#475,.T.);
#477=ORIENTED_EDGE('',*,*,#31,.T.);
#478=EDGE_LOOP('',(#477));
#479=FACE_BOUND('',#478,.T.);
#480=ADVANCED_FACE('F226',(#476,#479),#473,.F.);
#481=ORIENTED_EDGE('',*,*,#322,.F.);
#482=CARTESIAN_POINT('',(11.3005129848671,2.77726309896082,0.0691967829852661));
#483=CARTESIAN_POINT('',(11.3000098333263,2.7778376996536,0.04613118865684));
#484=CARTESIAN_POINT('',(11.2997582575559,2.77812499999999,0.0230655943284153));
#485=CARTESIAN_POINT('',(11.2997582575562,2.77812499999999,-0.0230655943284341));
#486=CARTESIAN_POINT('',(11.3000098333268,2.7778376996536,-0.0461311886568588));
#487=CARTESIAN_POINT('',(11.3005129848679,2.77726309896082,-0.0691967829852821));
#488=B_SPLINE_CURVE_WITH_KNOTS('',3,(#482,#483,#484,#485,#486,#487),.UNSPECIFIED.,.F.,.F.,(4,2,
4),(0.,0.0692062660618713,0.138412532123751),.UNSPECIFIED.);
#489=EDGE_CURVE('E208',#317,#321,#488,.T.);
#490=ORIENTED_EDGE('',*,*,#489,.T.);
#491=EDGE_LOOP('',(#481,#490));
#492=FACE_BOUND('',#491,.T.);
#493=ADVANCED_FACE('F220',(#492),#245,.F.);
#494=CARTESIAN_POINT('',(37.7444,0.,5.77596));
#495=DIRECTION('',(0.,0.,-1.));
#496=DIRECTION('',(-1.,0.,0.));
#497=AXIS2_PLACEMENT_3D('',#494,#495,#496);
#498=PLANE('',#497);
#499=ORIENTED_EDGE('',*,*,#59,.F.);
#500=EDGE_LOOP('',(#499));
#501=FACE_BOUND('',#500,.T.);
#502=CARTESIAN_POINT('',(33.528,0.,5.77596));
#503=DIRECTION('',(0.,0.,1.));
#504=DIRECTION('',(1.,0.,0.));
#505=AXIS2_PLACEMENT_3D('',#502,#503,#504);
#506=CIRCLE('',#505,4.93618496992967);
#507=CARTESIAN_POINT('',(38.4641849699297,0.,5.77596));
#508=VERTEX_POINT('',#507);
#509=EDGE_CURVE('E313',#508,#508,#506,.T.);
#510=ORIENTED_EDGE('',*,*,#509,.T.);
#511=EDGE_LOOP('',(#510));
#512=FACE_BOUND('',#511,.T.);
#513=ADVANCED_FACE('F225',(#501,#512),#498,.F.);
#514=CARTESIAN_POINT('',(33.528,0.,12.7));
#515=DIRECTION('',(0.,0.,1.));
#516=DIRECTION('',(1.,0.,0.));
#517=AXIS2_PLACEMENT_3D('',#514,#515,#516);
#518=CONICAL_SURFACE('',#517,5.1435,0.0299323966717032);
#519=ORIENTED_EDGE('',*,*,#509,.F.);
#520=EDGE_LOOP('',(#519));
#521=FACE_BOUND('',#520,.T.);
#522=CARTESIAN_POINT('',(33.528,0.,12.7));
#523=DIRECTION('',(0.,0.,1.));
#524=DIRECTION('',(1.,0.,0.));
#525=AXIS2_PLACEMENT_3D('',#522,#523,#524);
#526=CIRCLE('',#525,5.1435);
#527=CARTESIAN_POINT('',(38.6715,0.,12.7));
#528=VERTEX_POINT('',#527);
#529=EDGE_CURVE('E316',#528,#528,#526,.T.);
#530=ORIENTED_EDGE('',*,*,#529,.T.);
#531=EDGE_LOOP('',(#530));
#532=FACE_BOUND('',#531,.T.);
#533=ADVANCED_FACE('F186',(#521,#532),#518,.F.);
#534=CARTESIAN_POINT('',(42.0624,-14.6646968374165,0.));
#535=DIRECTION('',(0.,0.866025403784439,0.5));
#536=DIRECTION('',(0.,-0.5,0.866025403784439));
#537=AXIS2_PLACEMENT_3D('',#534,#535,#536);
#538=PLANE('',#537);
#539=DIRECTION('',(0.,0.5,-0.866025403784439));
#540=VECTOR('',#539,1.);
#541=CARTESIAN_POINT('',(0.,-14.6646968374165,0.));
#542=LINE('',#541,#540);
#543=CARTESIAN_POINT('',(0.,-14.6646968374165,0.));
#544=VERTEX_POINT('',#543);
#545=CARTESIAN_POINT('',(0.,-7.33234841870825,-12.7));
#546=VERTEX_POINT('',#545);
#547=EDGE_CURVE('E137',#544,#546,#542,.T.);
#548=ORIENTED_EDGE('',*,*,#547,.T.);
#549=DIRECTION('',(-1.,0.,0.));
#550=VECTOR('',#549,1.);
#551=CARTESIAN_POINT('',(42.0624,-7.33234841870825,-12.7));
#552=LINE('',#551,#550);
#553=CARTESIAN_POINT('',(42.0624,-7.33234841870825,-12.7));
#554=VERTEX_POINT('',#553);
#555=EDGE_CURVE('E150',#554,#546,#552,.T.);
#556=ORIENTED_EDGE('',*,*,#555,.F.);
#557=DIRECTION('',(0.,0.5,-0.866025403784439));
#558=VECTOR('',#557,1.);
#559=CARTESIAN_POINT('',(42.0624,-14.6646968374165,0.));
#560=LINE('',#559,#558);
#561=CARTESIAN_POINT('',(42.0624,-14.6646968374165,0.));
#562=VERTEX_POINT('',#561);
#563=EDGE_CURVE('E96',#562,#554,#560,.T.);
#564=ORIENTED_EDGE('',*,*,#563,.F.);
#565=DIRECTION('',(-1.,0.,0.));
#566=VECTOR('',#565,1.);
#567=CARTESIAN_POINT('',(42.0624,-14.6646968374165,0.));
#568=LINE('',#567,#566);
#569=EDGE_CURVE('E153',#562,#544,#568,.T.);
#570=ORIENTED_EDGE('',*,*,#569,.T.);
#571=EDGE_LOOP('',(#548,#556,#564,#570));
#572=FACE_BOUND('',#571,.T.);
#573=ADVANCED_FACE('F272',(#572),#538,.F.);
#574=CARTESIAN_POINT('',(42.0624,-7.33234841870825,-12.7));
#575=DIRECTION('',(0.,0.,1.));
#576=DIRECTION('',(1.,0.,0.));
#577=AXIS2_PLACEMENT_3D('',#574,#575,#576);
#578=PLANE('',#577);
#579=CARTESIAN_POINT('',(8.128,0.,-12.7));
#580=DIRECTION('',(0.,0.,-1.));
#581=DIRECTION('',(-1.,0.,0.));
#582=AXIS2_PLACEMENT_3D('',#579,#580,#581);
#583=CIRCLE('',#582,5.1435);
#584=CARTESIAN_POINT('',(2.9845,0.,-12.7));
#585=VERTEX_POINT('',#584);
#586=EDGE_CURVE('E386',#585,#585,#583,.T.);
#587=ORIENTED_EDGE('',*,*,#586,.F.);
#588=EDGE_LOOP('',(#587));
#589=FACE_BOUND('',#588,.T.);
#590=DIRECTION('',(0.,1.,0.));
#591=VECTOR('',#590,1.);
#592=CARTESIAN_POINT('',(0.,-7.33234841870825,-12.7));
#593=LINE('',#592,#591);
#594=CARTESIAN_POINT('',(0.,7.33234841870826,-12.7));
#595=VERTEX_POINT('',#594);
#596=EDGE_CURVE('E140',#546,#595,#593,.T.);
#597=ORIENTED_EDGE('',*,*,#596,.T.);
#598=DIRECTION('',(-1.,0.,0.));
#599=VECTOR('',#598,1.);
#600=CARTESIAN_POINT('',(42.0624,7.33234841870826,-12.7));
#601=LINE('',#600,#599);
#602=CARTESIAN_POINT('',(42.0624,7.33234841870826,-12.7));
#603=VERTEX_POINT('',#602);
#604=EDGE_CURVE('E125',#603,#595,#601,.T.);
#605=ORIENTED_EDGE('',*,*,#604,.F.);
#606=DIRECTION('',(0.,1.,0.));
#607=VECTOR('',#606,1.);
#608=CARTESIAN_POINT('',(42.0624,-7.33234841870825,-12.7));
#609=LINE('',#608,#607);
#610=EDGE_CURVE('E113',#554,#603,#609,.T.);
#611=ORIENTED_EDGE('',*,*,#610,.F.);
#612=ORIENTED_EDGE('',*,*,#555,.T.);
#613=EDGE_LOOP('',(#597,#605,#611,#612));
#614=FACE_BOUND('',#613,.T.);
#615=ADVANCED_FACE('F275',(#589,#614),#578,.F.);
#616=CARTESIAN_POINT('',(42.0624,7.33234841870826,-12.7));
#617=DIRECTION('',(0.,-0.866025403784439,0.5));
#618=DIRECTION('',(0.,-0.5,-0.866025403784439));
#619=AXIS2_PLACEMENT_3D('',#616,#617,#618);
#620=PLANE('',#619);
#621=DIRECTION('',(0.,0.5,0.866025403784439));
#622=VECTOR('',#621,1.);
#623=CARTESIAN_POINT('',(0.,7.33234841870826,-12.7));
#624=LINE('',#623,#622);
#625=CARTESIAN_POINT('',(0.,14.6646968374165,0.));
#626=VERTEX_POINT('',#625);
#627=EDGE_CURVE('E122',#595,#626,#624,.T.);
#628=ORIENTED_EDGE('',*,*,#627,.T.);
#629=DIRECTION('',(-1.,0.,0.));
#630=VECTOR('',#629,1.);
#631=CARTESIAN_POINT('',(42.0624,14.6646968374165,0.));
#632=LINE('',#631,#630);
#633=CARTESIAN_POINT('',(42.0624,14.6646968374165,0.));
#634=VERTEX_POINT('',#633);
#635=EDGE_CURVE('E119',#634,#626,#632,.T.);
#636=ORIENTED_EDGE('',*,*,#635,.F.);
#637=DIRECTION('',(0.,0.5,0.866025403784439));
#638=VECTOR('',#637,1.);
#639=CARTESIAN_POINT('',(42.0624,7.33234841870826,-12.7));
#640=LINE('',#639,#638);
#641=EDGE_CURVE('E105',#603,#634,#640,.T.);
#642=ORIENTED_EDGE('',*,*,#641,.F.);
#643=ORIENTED_EDGE('',*,*,#604,.T.);
#644=EDGE_LOOP('',(#628,#636,#642,#643));
#645=FACE_BOUND('',#644,.T.);
#646=ADVANCED_FACE('F120',(#645),#620,.F.);
#647=CARTESIAN_POINT('',(42.0624,14.6646968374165,0.));
#648=DIRECTION('',(0.,-0.866025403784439,-0.5));
#649=DIRECTION('',(0.,0.5,-0.866025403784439));
#650=AXIS2_PLACEMENT_3D('',#647,#648,#649);
#651=PLANE('',#650);
#652=DIRECTION('',(0.,-0.5,0.866025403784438));
#653=VECTOR('',#652,1.);
#654=CARTESIAN_POINT('',(0.,14.6646968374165,0.));
#655=LINE('',#654,#653);
#656=CARTESIAN_POINT('',(0.,7.33234841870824,12.7));
#657=VERTEX_POINT('',#656);
#658=EDGE_CURVE('E143',#626,#657,#655,.T.);
#659=ORIENTED_EDGE('',*,*,#658,.T.);
#660=DIRECTION('',(-1.,0.,0.));
#661=VECTOR('',#660,1.);
#662=CARTESIAN_POINT('',(42.0624,7.33234841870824,12.7));
#663=LINE('',#662,#661);
#664=CARTESIAN_POINT('',(42.0624,7.33234841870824,12.7));
#665=VERTEX_POINT('',#664);
#666=EDGE_CURVE('E126',#665,#657,#663,.T.);
#667=ORIENTED_EDGE('',*,*,#666,.F.);
#668=DIRECTION('',(0.,-0.5,0.866025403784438));
#669=VECTOR('',#668,1.);
#670=CARTESIAN_POINT('',(42.0624,14.6646968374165,0.));
#671=LINE('',#670,#669);
#672=EDGE_CURVE('E110',#634,#665,#671,.T.);
#673=ORIENTED_EDGE('',*,*,#672,.F.);
#674=ORIENTED_EDGE('',*,*,#635,.T.);
#675=EDGE_LOOP('',(#659,#667,#673,#674));
#676=FACE_BOUND('',#675,.T.);
#677=ADVANCED_FACE('F128',(#676),#651,.F.);
#678=CARTESIAN_POINT('',(42.0624,-14.6646968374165,0.));
#679=DIRECTION('',(1.,0.,0.));
#680=DIRECTION('',(0.,0.,-1.));
#681=AXIS2_PLACEMENT_3D('',#678,#679,#680);
#682=PLANE('',#681);
#683=DIRECTION('',(0.,-0.5,-0.866025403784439));
#684=VECTOR('',#683,1.);
#685=CARTESIAN_POINT('',(42.0624,-7.33234841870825,12.7));
#686=LINE('',#685,#684);
#687=CARTESIAN_POINT('',(42.0624,-7.33234841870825,12.7));
#688=VERTEX_POINT('',#687);
#689=EDGE_CURVE('E146',#688,#562,#686,.T.);
#690=ORIENTED_EDGE('',*,*,#689,.T.);
#691=ORIENTED_EDGE('',*,*,#563,.T.);
#692=ORIENTED_EDGE('',*,*,#610,.T.);
#693=ORIENTED_EDGE('',*,*,#641,.T.);
#694=ORIENTED_EDGE('',*,*,#672,.T.);
#695=DIRECTION('',(0.,-1.,0.));
#696=VECTOR('',#695,1.);
#697=CARTESIAN_POINT('',(42.0624,7.33234841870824,12.7));
#698=LINE('',#697,#696);
#699=EDGE_CURVE('E60',#665,#688,#698,.T.);
#700=ORIENTED_EDGE('',*,*,#699,.T.);
#701=EDGE_LOOP('',(#690,#691,#692,#693,#694,#700));
#702=FACE_BOUND('',#701,.T.);
#703=CARTESIAN_POINT('',(42.0624,0.,0.));
#704=DIRECTION('',(1.,0.,0.));
#705=DIRECTION('',(0.,0.,-1.));
#706=AXIS2_PLACEMENT_3D('',#703,#704,#705);
#707=CIRCLE('',#706,11.1125);
#708=CARTESIAN_POINT('',(42.0624,0.,11.1125));
#709=VERTEX_POINT('',#708);
#710=EDGE_CURVE('E138',#709,#709,#707,.F.);
#711=ORIENTED_EDGE('',*,*,#710,.T.);
#712=EDGE_LOOP('',(#711));
#713=FACE_BOUND('',#712,.T.);
#714=ADVANCED_FACE('F107',(#702,#713),#682,.T.);
#715=CARTESIAN_POINT('',(42.0624,-7.33234841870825,12.7));
#716=DIRECTION('',(0.,0.866025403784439,-0.5));
#717=DIRECTION('',(0.,0.5,0.866025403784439));
#718=AXIS2_PLACEMENT_3D('',#715,#716,#717);
#719=PLANE('',#718);
#720=DIRECTION('',(0.,-0.5,-0.866025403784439));
#721=VECTOR('',#720,1.);
#722=CARTESIAN_POINT('',(0.,-7.33234841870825,12.7));
#723=LINE('',#722,#721);
#724=CARTESIAN_POINT('',(0.,-7.33234841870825,12.7));
#725=VERTEX_POINT('',#724);
#726=EDGE_CURVE('E134',#725,#544,#723,.T.);
#727=ORIENTED_EDGE('',*,*,#726,.T.);
#728=ORIENTED_EDGE('',*,*,#569,.F.);
#729=ORIENTED_EDGE('',*,*,#689,.F.);
#730=DIRECTION('',(-1.,0.,0.));
#731=VECTOR('',#730,1.);
#732=CARTESIAN_POINT('',(42.0624,-7.33234841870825,12.7));
#733=LINE('',#732,#731);
#734=EDGE_CURVE('E130',#688,#725,#733,.T.);
#735=ORIENTED_EDGE('',*,*,#734,.T.);
#736=EDGE_LOOP('',(#727,#728,#729,#735));
#737=FACE_BOUND('',#736,.T.);
#738=ADVANCED_FACE('F36',(#737),#719,.F.);
#739=CARTESIAN_POINT('',(0.,-14.6646968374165,0.));
#740=DIRECTION('',(1.,0.,0.));
#741=DIRECTION('',(0.,0.,-1.));
#742=AXIS2_PLACEMENT_3D('',#739,#740,#741);
#743=PLANE('',#742);
#744=ORIENTED_EDGE('',*,*,#726,.F.);
#745=DIRECTION('',(0.,-1.,0.));
#746=VECTOR('',#745,1.);
#747=CARTESIAN_POINT('',(0.,7.33234841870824,12.7));
#748=LINE('',#747,#746);
#749=EDGE_CURVE('E87',#657,#725,#748,.T.);
#750=ORIENTED_EDGE('',*,*,#749,.F.);
#751=ORIENTED_EDGE('',*,*,#658,.F.);
#752=ORIENTED_EDGE('',*,*,#627,.F.);
#753=ORIENTED_EDGE('',*,*,#596,.F.);
#754=ORIENTED_EDGE('',*,*,#547,.F.);
#755=EDGE_LOOP('',(#744,#750,#751,#752,#753,#754));
#756=FACE_BOUND('',#755,.T.);
#757=ADVANCED_FACE('F278',(#756),#743,.F.);
#758=CARTESIAN_POINT('',(42.0624,7.33234841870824,12.7));
#759=DIRECTION('',(0.,0.,-1.));
#760=DIRECTION('',(0.,1.,0.));
#761=AXIS2_PLACEMENT_3D('',#758,#759,#760);
#762=PLANE('',#761);
#763=CARTESIAN_POINT('',(8.128,0.,12.7));
#764=DIRECTION('',(0.,0.,1.));
#765=DIRECTION('',(1.,0.,0.));
#766=AXIS2_PLACEMENT_3D('',#763,#764,#765);
#767=CIRCLE('',#766,5.1435);
#768=CARTESIAN_POINT('',(13.2715,0.,12.7));
#769=VERTEX_POINT('',#768);
#770=EDGE_CURVE('E409',#769,#769,#767,.T.);
#771=ORIENTED_EDGE('',*,*,#770,.F.);
#772=EDGE_LOOP('',(#771));
#773=FACE_BOUND('',#772,.T.);
#774=ORIENTED_EDGE('',*,*,#529,.F.);
#775=EDGE_LOOP('',(#774));
#776=FACE_BOUND('',#775,.T.);
#777=ORIENTED_EDGE('',*,*,#749,.T.);
#778=ORIENTED_EDGE('',*,*,#734,.F.);
#779=ORIENTED_EDGE('',*,*,#699,.F.);
#780=ORIENTED_EDGE('',*,*,#666,.T.);
#781=EDGE_LOOP('',(#777,#778,#779,#780));
#782=FACE_BOUND('',#781,.T.);
#783=ADVANCED_FACE('F279',(#773,#776,#782),#762,.F.);
#784=CARTESIAN_POINT('',(52.9844,0.,0.));
#785=DIRECTION('',(-1.,0.,0.));
#786=DIRECTION('',(0.,0.,1.));
#787=AXIS2_PLACEMENT_3D('',#784,#785,#786);
#788=CYLINDRICAL_SURFACE('',#787,11.1125);
#789=CARTESIAN_POINT('',(42.0624,0.,11.1125));
#790=CARTESIAN_POINT('',(42.1761708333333,0.,11.1125));
#791=CARTESIAN_POINT('',(42.2899416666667,0.,11.1125));
#792=CARTESIAN_POINT('',(42.5174833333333,0.,11.1125));
#793=CARTESIAN_POINT('',(42.6312541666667,0.,11.1125));
#794=CARTESIAN_POINT('',(42.8587958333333,0.,11.1125));
#795=CARTESIAN_POINT('',(42.9725666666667,0.,11.1125));
#796=CARTESIAN_POINT('',(43.2001083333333,0.,11.1125));
#797=CARTESIAN_POINT('',(43.3138791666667,0.,11.1125));
#798=CARTESIAN_POINT('',(43.5414208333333,0.,11.1125));
#799=CARTESIAN_POINT('',(43.6551916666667,0.,11.1125));
#800=CARTESIAN_POINT('',(43.8827333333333,0.,11.1125));
#801=CARTESIAN_POINT('',(43.9965041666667,0.,11.1125));
#802=CARTESIAN_POINT('',(44.2240458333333,0.,11.1125));
#803=CARTESIAN_POINT('',(44.3378166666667,0.,11.1125));
#804=CARTESIAN_POINT('',(44.5653583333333,0.,11.1125));
#805=CARTESIAN_POINT('',(44.6791291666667,0.,11.1125));
#806=CARTESIAN_POINT('',(44.9066708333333,0.,11.1125));
#807=CARTESIAN_POINT('',(45.0204416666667,0.,11.1125));
#808=CARTESIAN_POINT('',(45.2479833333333,0.,11.1125));
#809=CARTESIAN_POINT('',(45.3617541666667,0.,11.1125));
#810=CARTESIAN_POINT('',(45.5892958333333,0.,11.1125));
#811=CARTESIAN_POINT('',(45.7030666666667,0.,11.1125));
#812=CARTESIAN_POINT('',(45.9306083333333,0.,11.1125));
#813=CARTESIAN_POINT('',(46.0443791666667,0.,11.1125));
#814=CARTESIAN_POINT('',(46.2719208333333,0.,11.1125));
#815=CARTESIAN_POINT('',(46.3856916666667,0.,11.1125));
#816=CARTESIAN_POINT('',(46.6132333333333,0.,11.1125));
#817=CARTESIAN_POINT('',(46.7270041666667,0.,11.1125));
#818=CARTESIAN_POINT('',(46.9545458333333,0.,11.1125));
#819=CARTESIAN_POINT('',(47.0683166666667,0.,11.1125));
#820=CARTESIAN_POINT('',(47.2958583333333,0.,11.1125));
#821=CARTESIAN_POINT('',(47.4096291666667,0.,11.1125));
#822=CARTESIAN_POINT('',(47.6371708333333,0.,11.1125));
#823=CARTESIAN_POINT('',(47.7509416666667,0.,11.1125));
#824=CARTESIAN_POINT('',(47.9784833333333,0.,11.1125));
#825=CARTESIAN_POINT('',(48.0922541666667,0.,11.1125));
#826=CARTESIAN_POINT('',(48.3197958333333,0.,11.1125));
#827=CARTESIAN_POINT('',(48.4335666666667,0.,11.1125));
#828=CARTESIAN_POINT('',(48.6611083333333,0.,11.1125));
#829=CARTESIAN_POINT('',(48.7748791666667,0.,11.1125));
#830=CARTESIAN_POINT('',(49.0024208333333,0.,11.1125));
#831=CARTESIAN_POINT('',(49.1161916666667,0.,11.1125));
#832=CARTESIAN_POINT('',(49.3437333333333,0.,11.1125));
#833=CARTESIAN_POINT('',(49.4575041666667,0.,11.1125));
#834=CARTESIAN_POINT('',(49.6850458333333,0.,11.1125));
#835=CARTESIAN_POINT('',(49.7988166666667,0.,11.1125));
#836=CARTESIAN_POINT('',(50.0263583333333,0.,11.1125));
#837=CARTESIAN_POINT('',(50.1401291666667,0.,11.1125));
#838=CARTESIAN_POINT('',(50.3676708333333,0.,11.1125));
#839=CARTESIAN_POINT('',(50.4814416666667,0.,11.1125));
#840=CARTESIAN_POINT('',(50.7089833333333,0.,11.1125));
#841=CARTESIAN_POINT('',(50.8227541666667,0.,11.1125));
#842=CARTESIAN_POINT('',(51.0502958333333,0.,11.1125));
#843=CARTESIAN_POINT('',(51.1640666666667,0.,11.1125));
#844=CARTESIAN_POINT('',(51.3916083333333,0.,11.1125));
#845=CARTESIAN_POINT('',(51.5053791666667,0.,11.1125));
#846=CARTESIAN_POINT('',(51.7329208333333,0.,11.1125));
#847=CARTESIAN_POINT('',(51.8466916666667,0.,11.1125));
#848=CARTESIAN_POINT('',(52.0742333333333,0.,11.1125));
#849=CARTESIAN_POINT('',(52.1880041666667,0.,11.1125));
#850=CARTESIAN_POINT('',(52.4155458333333,0.,11.1125));
#851=CARTESIAN_POINT('',(52.5293166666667,0.,11.1125));
#852=CARTESIAN_POINT('',(52.7568583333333,0.,11.1125));
#853=CARTESIAN_POINT('',(52.8706291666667,0.,11.1125));
#854=CARTESIAN_POINT('',(52.9844,0.,11.1125));
#855=B_SPLINE_CURVE_WITH_KNOTS('',3,(#789,#790,#791,#792,#793,#794,#795,#796,#797,#798,#799,
#800,#801,#802,#803,#804,#805,#806,#807,#808,#809,#810,#811,#812,#813,#814,#815,#816,#817,#818,
#819,#820,#821,#822,#823,#824,#825,#826,#827,#828,#829,#830,#831,#832,#833,#834,#835,#836,#837,
#838,#839,#840,#841,#842,#843,#844,#845,#846,#847,#848,#849,#850,#851,#852,#853,#854),
.UNSPECIFIED.,.F.,.F.,(4,2,2,2,2,2,2,2,2,2,2,2,2,2,2,2,2,2,2,2,2,2,2,2,2,2,2,2,2,2,2,2,4),(0.,
0.341312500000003,0.682624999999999,1.0239375,1.36525000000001,1.7065625,2.047875,2.3891875,
2.7305,3.0718125,3.413125,3.7544375,4.09575,4.4370625,4.778375,5.1196875,5.461,5.8023125,
6.143625,6.4849375,6.82625,7.1675625,7.508875,7.8501875,8.1915,8.5328125,8.874125,9.2154375,
9.55675,9.8980625,10.239375,10.5806875,10.922),.UNSPECIFIED.);
#856=EDGE_CURVE('BSEAM183',#709,#224,#855,.T.);
#857=ORIENTED_EDGE('',*,*,#710,.F.);
#858=ORIENTED_EDGE('',*,*,#225,.F.);
#859=ORIENTED_EDGE('',*,*,#856,.T.);
#860=ORIENTED_EDGE('',*,*,#856,.F.);
#861=EDGE_LOOP('',(#857,#859,#858,#860));
#862=FACE_BOUND('',#861,.T.);
#863=ADVANCED_FACE('F183',(#862),#788,.T.);
#864=CARTESIAN_POINT('',(8.128,0.,12.7));
#865=DIRECTION('',(0.,0.,1.));
#866=DIRECTION('',(1.,0.,0.));
#867=AXIS2_PLACEMENT_3D('',#864,#865,#866);
#868=CYLINDRICAL_SURFACE('',#867,4.2164);
#869=CARTESIAN_POINT('',(8.128,0.,5.77596));
#870=DIRECTION('',(0.,0.,1.));
#871=DIRECTION('',(1.,0.,0.));
#872=AXIS2_PLACEMENT_3D('',#869,#870,#871);
#873=CIRCLE('',#872,4.2164);
#874=CARTESIAN_POINT('',(12.3444,0.,5.77596));
#875=VERTEX_POINT('',#874);
#876=EDGE_CURVE('E414',#875,#875,#873,.T.);
#877=ORIENTED_EDGE('',*,*,#876,.T.);
#878=EDGE_LOOP('',(#877));
#879=FACE_BOUND('',#878,.T.);
#880=ORIENTED_EDGE('',*,*,#318,.F.);
#881=ORIENTED_EDGE('',*,*,#415,.F.);
#882=ORIENTED_EDGE('',*,*,#369,.F.);
#883=ORIENTED_EDGE('',*,*,#264,.F.);
#884=ORIENTED_EDGE('',*,*,#366,.F.);
#885=ORIENTED_EDGE('',*,*,#453,.F.);
#886=ORIENTED_EDGE('',*,*,#324,.F.);
#887=ORIENTED_EDGE('',*,*,#489,.F.);
#888=EDGE_LOOP('',(#880,#881,#882,#883,#884,#885,#886,#887));
#889=FACE_BOUND('',#888,.T.);
#890=CARTESIAN_POINT('',(8.128,0.,-5.77596));
#891=DIRECTION('',(0.,0.,-1.));
#892=DIRECTION('',(-1.,0.,0.));
#893=AXIS2_PLACEMENT_3D('',#890,#891,#892);
#894=CIRCLE('',#893,4.21640000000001);
#895=CARTESIAN_POINT('',(3.91159999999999,0.,-5.77596));
#896=VERTEX_POINT('',#895);
#897=EDGE_CURVE('E406',#896,#896,#894,.T.);
#898=ORIENTED_EDGE('',*,*,#897,.T.);
#899=EDGE_LOOP('',(#898));
#900=FACE_BOUND('',#899,.T.);
#901=ADVANCED_FACE('F177',(#879,#889,#900),#868,.F.);
#902=CARTESIAN_POINT('',(12.3444,0.,5.77596));
#903=DIRECTION('',(0.,0.,-1.));
#904=DIRECTION('',(-1.,0.,0.));
#905=AXIS2_PLACEMENT_3D('',#902,#903,#904);
#906=PLANE('',#905);
#907=ORIENTED_EDGE('',*,*,#876,.F.);
#908=EDGE_LOOP('',(#907));
#909=FACE_BOUND('',#908,.T.);
#910=CARTESIAN_POINT('',(8.128,0.,5.77596));
#911=DIRECTION('',(0.,0.,1.));
#912=DIRECTION('',(1.,0.,0.));
#913=AXIS2_PLACEMENT_3D('',#910,#911,#912);
#914=CIRCLE('',#913,4.93618496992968);
#915=CARTESIAN_POINT('',(13.0641849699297,0.,5.77596));
#916=VERTEX_POINT('',#915);
#917=EDGE_CURVE('E412',#916,#916,#914,.T.);
#918=ORIENTED_EDGE('',*,*,#917,.T.);
#919=EDGE_LOOP('',(#918));
#920=FACE_BOUND('',#919,.T.);
#921=ADVANCED_FACE('F182',(#909,#920),#906,.F.);
#922=CARTESIAN_POINT('',(8.128,0.,12.7));
#923=DIRECTION('',(0.,0.,1.));
#924=DIRECTION('',(1.,0.,0.));
#925=AXIS2_PLACEMENT_3D('',#922,#923,#924);
#926=CONICAL_SURFACE('',#925,5.1435,0.0299323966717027);
#927=ORIENTED_EDGE('',*,*,#917,.F.);
#928=EDGE_LOOP('',(#927));
#929=FACE_BOUND('',#928,.T.);
#930=ORIENTED_EDGE('',*,*,#770,.T.);
#931=EDGE_LOOP('',(#930));
#932=FACE_BOUND('',#931,.T.);
#933=ADVANCED_FACE('F430',(#929,#932),#926,.F.);
#934=CARTESIAN_POINT('',(12.3444,0.,-5.77596));
#935=DIRECTION('',(0.,0.,1.));
#936=DIRECTION('',(1.,0.,0.));
#937=AXIS2_PLACEMENT_3D('',#934,#935,#936);
#938=PLANE('',#937);
#939=ORIENTED_EDGE('',*,*,#897,.F.);
#940=EDGE_LOOP('',(#939));
#941=FACE_BOUND('',#940,.T.);
#942=CARTESIAN_POINT('',(8.128,0.,-5.77596));
#943=DIRECTION('',(0.,0.,-1.));
#944=DIRECTION('',(-1.,0.,0.));
#945=AXIS2_PLACEMENT_3D('',#942,#943,#944);
#946=CIRCLE('',#945,4.93618496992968);
#947=CARTESIAN_POINT('',(3.19181503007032,0.,-5.77596));
#948=VERTEX_POINT('',#947);
#949=EDGE_CURVE('E403',#948,#948,#946,.T.);
#950=ORIENTED_EDGE('',*,*,#949,.T.);
#951=EDGE_LOOP('',(#950));
#952=FACE_BOUND('',#951,.T.);
#953=ADVANCED_FACE('F426',(#941,#952),#938,.F.);
#954=CARTESIAN_POINT('',(8.128,0.,-12.7));
#955=DIRECTION('',(0.,0.,-1.));
#956=DIRECTION('',(-1.,0.,0.));
#957=AXIS2_PLACEMENT_3D('',#954,#955,#956);
#958=CONICAL_SURFACE('',#957,5.1435,0.0299323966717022);
#959=ORIENTED_EDGE('',*,*,#949,.F.);
#960=EDGE_LOOP('',(#959));
#961=FACE_BOUND('',#960,.T.);
#962=ORIENTED_EDGE('',*,*,#586,.T.);
#963=EDGE_LOOP('',(#962));
#964=FACE_BOUND('',#963,.T.);
#965=ADVANCED_FACE('F429',(#961,#964),#958,.F.);
#966=CARTESIAN_POINT('',(27.5844,0.,0.));
#967=DIRECTION('',(1.,0.,0.));
#968=DIRECTION('',(0.,0.,-1.));
#969=AXIS2_PLACEMENT_3D('',#966,#967,#968);
#970=PLANE('',#969);
#971=CARTESIAN_POINT('',(27.5844,0.,0.));
#972=DIRECTION('',(-1.,0.,0.));
#973=DIRECTION('',(0.,0.,1.));
#974=AXIS2_PLACEMENT_3D('',#971,#972,#973);
#975=CIRCLE('',#974,5.54990000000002);
#976=CARTESIAN_POINT('',(27.5844,0.,5.54990000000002));
#977=VERTEX_POINT('',#976);
#978=EDGE_CURVE('E392',#977,#977,#975,.T.);
#979=ORIENTED_EDGE('',*,*,#978,.F.);
#980=EDGE_LOOP('',(#979));
#981=FACE_BOUND('',#980,.T.);
#982=ORIENTED_EDGE('',*,*,#42,.T.);
#983=EDGE_LOOP('',(#982));
#984=FACE_BOUND('',#983,.T.);
#985=ADVANCED_FACE('F369',(#981,#984),#970,.T.);
#986=CARTESIAN_POINT('',(0.,0.,0.));
#987=DIRECTION('',(-1.,0.,0.));
#988=DIRECTION('',(0.,0.,1.));
#989=AXIS2_PLACEMENT_3D('',#986,#987,#988);
#990=CYLINDRICAL_SURFACE('',#989,5.54990000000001);
#991=ORIENTED_EDGE('',*,*,#978,.T.);
#992=EDGE_LOOP('',(#991));
#993=FACE_BOUND('',#992,.T.);
#994=CARTESIAN_POINT('',(45.0596,0.,0.));
#995=DIRECTION('',(-1.,0.,0.));
#996=DIRECTION('',(0.,0.,1.));
#997=AXIS2_PLACEMENT_3D('',#994,#995,#996);
#998=CIRCLE('',#997,5.54990000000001);
#999=CARTESIAN_POINT('',(45.0596,0.,5.54990000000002));
#1000=VERTEX_POINT('',#999);
#1001=EDGE_CURVE('E397',#1000,#1000,#998,.T.);
#1002=ORIENTED_EDGE('',*,*,#1001,.F.);
#1003=EDGE_LOOP('',(#1002));
#1004=FACE_BOUND('',#1003,.T.);
#1005=ORIENTED_EDGE('',*,*,#208,.T.);
#1006=EDGE_LOOP('',(#1005));
#1007=FACE_BOUND('',#1006,.T.);
#1008=CARTESIAN_POINT('',(37.7444,0.,-5.54990000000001));
#1009=CARTESIAN_POINT('',(37.7443993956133,-0.102666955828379,-5.54989942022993));
#1010=CARTESIAN_POINT('',(37.7406438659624,-0.205343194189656,-5.54704470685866));
#1011=CARTESIAN_POINT('',(37.7256842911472,-0.409877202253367,-5.53569249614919));
#1012=CARTESIAN_POINT('',(37.7144766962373,-0.511734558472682,-5.52719230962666));
#1013=CARTESIAN_POINT('',(37.6847756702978,-0.713930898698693,-5.50472974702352));
#1014=CARTESIAN_POINT('',(37.6662712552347,-0.814267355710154,-5.49075913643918));
#1015=CARTESIAN_POINT('',(37.6222775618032,-1.01254840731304,-5.45767930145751));
#1016=CARTESIAN_POINT('',(37.5967851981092,-1.11049192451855,-5.4385678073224));
#1017=CARTESIAN_POINT('',(37.5107274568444,-1.398497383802,-5.37438339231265));
#1018=CARTESIAN_POINT('',(37.440361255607,-1.58418379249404,-5.32229076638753));
#1019=CARTESIAN_POINT('',(37.276841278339,-1.93974746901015,-5.20327185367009));
#1020=CARTESIAN_POINT('',(37.1836912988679,-2.10962736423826,-5.13634803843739));
#1021=CARTESIAN_POINT('',(36.9680945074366,-2.44693461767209,-4.98509307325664));
#1022=CARTESIAN_POINT('',(36.8437265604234,-2.61265837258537,-4.89972096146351));
#1023=CARTESIAN_POINT('',(36.5743774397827,-2.92229860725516,-4.72159970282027));
#1024=CARTESIAN_POINT('',(36.4293655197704,-3.06618188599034,-4.62883964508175));
#1025=CARTESIAN_POINT('',(36.1818679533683,-3.27873581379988,-4.47894046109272));
#1026=CARTESIAN_POINT('',(36.0852396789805,-3.35465016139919,-4.42221951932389));
#1027=CARTESIAN_POINT('',(35.8853172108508,-3.49803153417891,-4.30969399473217));
#1028=CARTESIAN_POINT('',(35.7820209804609,-3.56549595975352,-4.25388969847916));
#1029=CARTESIAN_POINT('',(35.5689644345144,-3.69158445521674,-4.14494021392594));
#1030=CARTESIAN_POINT('',(35.459210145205,-3.75021659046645,-4.09179262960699));
#1031=CARTESIAN_POINT('',(35.2332788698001,-3.85820397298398,-3.99013143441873));
#1032=CARTESIAN_POINT('',(35.1171056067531,-3.90756452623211,-3.94161518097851));
#1033=CARTESIAN_POINT('',(34.8423535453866,-4.00972513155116,-3.8380021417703));
#1034=CARTESIAN_POINT('',(34.6815147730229,-4.05910874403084,-3.78530268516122));
#1035=CARTESIAN_POINT('',(34.4334747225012,-4.11890503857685,-3.71979682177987));
#1036=CARTESIAN_POINT('',(34.3497154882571,-4.13645117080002,-3.70022626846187));
#1037=CARTESIAN_POINT('',(34.1802742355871,-4.16652842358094,-3.66632583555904));
#1038=CARTESIAN_POINT('',(34.0945932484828,-4.17906216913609,-3.65199321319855));
#1039=CARTESIAN_POINT('',(33.9209530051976,-4.19896788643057,-3.62908998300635));
#1040=CARTESIAN_POINT('',(33.8329793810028,-4.2062854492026,-3.62058014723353));
#1041=CARTESIAN_POINT('',(33.6563570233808,-4.2153732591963,-3.60999553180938));
#1042=CARTESIAN_POINT('',(33.5677083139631,-4.21714370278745,-3.60792052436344));
#1043=CARTESIAN_POINT('',(33.3905433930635,-4.21508975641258,-3.61032018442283));
#1044=CARTESIAN_POINT('',(33.3020272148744,-4.21126414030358,-3.61479628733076));
#1045=CARTESIAN_POINT('',(33.1259748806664,-4.1981195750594,-3.63005192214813));
#1046=CARTESIAN_POINT('',(33.0384387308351,-4.18880059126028,-3.64083149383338));
#1047=CARTESIAN_POINT('',(32.7985166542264,-4.15568903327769,-3.67868158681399));
#1048=CARTESIAN_POINT('',(32.6478348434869,-4.1262776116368,-3.71190594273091));
#1049=CARTESIAN_POINT('',(32.3540921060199,-4.05253036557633,-3.79227022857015));
#1050=CARTESIAN_POINT('',(32.211039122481,-4.00817932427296,-3.83942434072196));
#1051=CARTESIAN_POINT('',(31.9583831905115,-3.91523448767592,-3.93394303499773));
#1052=CARTESIAN_POINT('',(31.847374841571,-3.86881960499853,-3.97976043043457));
#1053=CARTESIAN_POINT('',(31.6311954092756,-3.76754813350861,-4.07576238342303));
#1054=CARTESIAN_POINT('',(31.5260274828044,-3.71268703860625,-4.12594926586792));
#1055=CARTESIAN_POINT('',(31.3214051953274,-3.59484859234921,-4.22901830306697));
#1056=CARTESIAN_POINT('',(31.2219633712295,-3.53185434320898,-4.28190592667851));
#1057=CARTESIAN_POINT('',(31.0290973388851,-3.39812936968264,-4.38878526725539));
#1058=CARTESIAN_POINT('',(30.9356721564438,-3.32739990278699,-4.44277680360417));
#1059=CARTESIAN_POINT('',(30.75235900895,-3.17621734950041,-4.5521400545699));
#1060=CARTESIAN_POINT('',(30.6626496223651,-3.0955433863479,-4.6075068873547));
#1061=CARTESIAN_POINT('',(30.4900225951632,-2.92631985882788,-4.71680129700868));
#1062=CARTESIAN_POINT('',(30.4071076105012,-2.83776724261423,-4.77072830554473));
#1063=CARTESIAN_POINT('',(30.1695373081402,-2.5608184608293,-4.92833957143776));
#1064=CARTESIAN_POINT('',(30.0255232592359,-2.36069403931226,-5.02818332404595));
#1065=CARTESIAN_POINT('',(29.79622654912,-1.97290355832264,-5.19079382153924));
#1066=CARTESIAN_POINT('',(29.704976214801,-1.7902262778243,-5.25699864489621));
#1067=CARTESIAN_POINT('',(29.5877201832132,-1.50428240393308,-5.34307696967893));
#1068=CARTESIAN_POINT('',(29.5518975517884,-1.40695118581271,-5.36957042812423));
#1069=CARTESIAN_POINT('',(29.487255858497,-1.20882529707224,-5.41761054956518));
#1070=CARTESIAN_POINT('',(29.4584337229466,-1.10803216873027,-5.43915938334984));
#1071=CARTESIAN_POINT('',(29.4080388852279,-0.902877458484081,-5.47696644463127));
#1072=CARTESIAN_POINT('',(29.3865198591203,-0.798495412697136,-5.49318547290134));
#1073=CARTESIAN_POINT('',(29.3513945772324,-0.587711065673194,-5.51971567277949));
#1074=CARTESIAN_POINT('',(29.3377846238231,-0.481309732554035,-5.53002960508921));
#1075=CARTESIAN_POINT('',(29.3187165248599,-0.267379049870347,-5.54449183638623));
#1076=CARTESIAN_POINT('',(29.3132569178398,-0.159849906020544,-5.54864124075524));
#1077=CARTESIAN_POINT('',(29.31059043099,0.0553630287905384,-5.55066695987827));
#1078=CARTESIAN_POINT('',(29.3133828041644,0.163046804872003,-5.54854384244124));
#1079=CARTESIAN_POINT('',(29.3264157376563,0.365919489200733,-5.53865106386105));
#1080=CARTESIAN_POINT('',(29.3358141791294,0.461194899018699,-5.53151989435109));
#1081=CARTESIAN_POINT('',(29.3609746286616,0.650427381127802,-5.51247648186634));
#1082=CARTESIAN_POINT('',(29.3767386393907,0.744384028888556,-5.50056273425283));
#1083=CARTESIAN_POINT('',(29.4332697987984,1.02327908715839,-5.4579792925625));
#1084=CARTESIAN_POINT('',(29.4832871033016,1.20540685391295,-5.42045882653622));
#1085=CARTESIAN_POINT('',(29.6070842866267,1.56242729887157,-5.32871242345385));
#1086=CARTESIAN_POINT('',(29.681457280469,1.73700152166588,-5.27407116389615));
#1087=CARTESIAN_POINT('',(29.8505450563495,2.07109183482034,-5.15204916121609));
#1088=CARTESIAN_POINT('',(29.9452628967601,2.23060565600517,-5.08466650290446));
#1089=CARTESIAN_POINT('',(30.1694079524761,2.55802504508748,-4.92909083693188));
#1090=CARTESIAN_POINT('',(30.3019810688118,2.72300325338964,-4.83929765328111));
#1091=CARTESIAN_POINT('',(30.5883037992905,3.02991540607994,-4.65330404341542));
#1092=CARTESIAN_POINT('',(30.7420960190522,3.1718017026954,-4.55709093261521));
#1093=CARTESIAN_POINT('',(31.0034639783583,3.37940703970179,-4.40345363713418));
#1094=CARTESIAN_POINT('',(31.1049126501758,3.45288781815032,-4.34591141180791));
#1095=CARTESIAN_POINT('',(31.314685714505,3.59096735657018,-4.23253042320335));
#1096=CARTESIAN_POINT('',(31.4230125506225,3.65556293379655,-4.17669227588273));
#1097=CARTESIAN_POINT('',(31.6462598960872,3.77532660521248,-4.06875742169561));
#1098=CARTESIAN_POINT('',(31.7611678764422,3.83051186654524,-4.01665400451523));
#1099=CARTESIAN_POINT('',(31.9975785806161,3.93094643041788,-3.91841531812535));
#1100=CARTESIAN_POINT('',(32.1190762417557,3.97620322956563,-3.8722755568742));
#1101=CARTESIAN_POINT('',(32.3974988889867,4.06520982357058,-3.7789612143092));
#1102=CARTESIAN_POINT('',(32.5561211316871,4.10619306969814,-3.7340128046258));
#1103=CARTESIAN_POINT('',(32.7996105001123,4.15383268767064,-3.6807099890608));
#1104=CARTESIAN_POINT('',(32.8816471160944,4.16740255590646,-3.66530086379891));
#1105=CARTESIAN_POINT('',(33.0471718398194,4.18972486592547,-3.63976459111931));
#1106=CARTESIAN_POINT('',(33.1306592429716,4.19847958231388,-3.62963494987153));
#1107=CARTESIAN_POINT('',(33.2991320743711,4.21103758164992,-3.61505835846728));
#1108=CARTESIAN_POINT('',(33.3841240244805,4.21480358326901,-3.61065420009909));
#1109=CARTESIAN_POINT('',(33.5542775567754,4.21717640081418,-3.60788260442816));
#1110=CARTESIAN_POINT('',(33.639439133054,4.21578339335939,-3.60951496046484));
#1111=CARTESIAN_POINT('',(33.8092521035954,4.20786839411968,-3.61873867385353));
#1112=CARTESIAN_POINT('',(33.8939031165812,4.20134295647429,-3.62633403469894));
#1113=CARTESIAN_POINT('',(34.0620056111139,4.18330254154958,-3.64713005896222));
#1114=CARTESIAN_POINT('',(34.1454564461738,4.1717849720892,-3.66033363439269));
#1115=CARTESIAN_POINT('',(34.3240534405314,4.14171556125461,-3.69434379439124));
#1116=CARTESIAN_POINT('',(34.4188890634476,4.12232321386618,-3.71603879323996));
#1117=CARTESIAN_POINT('',(34.6056232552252,4.07749843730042,-3.76516999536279));
#1118=CARTESIAN_POINT('',(34.697519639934,4.05206162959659,-3.79261035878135));
#1119=CARTESIAN_POINT('',(34.9685718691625,3.96719813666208,-3.88193715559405));
#1120=CARTESIAN_POINT('',(35.1428493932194,3.89926066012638,-3.95077814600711));
#1121=CARTESIAN_POINT('',(35.4260549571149,3.76720881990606,-4.07616702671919));
#1122=CARTESIAN_POINT('',(35.5387046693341,3.70824622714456,-4.13006200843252));
#1123=CARTESIAN_POINT('',(35.7572672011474,3.58111275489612,-4.24076863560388));
#1124=CARTESIAN_POINT('',(35.8631775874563,3.51293857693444,-4.29758132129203));
#1125=CARTESIAN_POINT('',(36.0681950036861,3.36767607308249,-4.41233843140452));
#1126=CARTESIAN_POINT('',(36.167295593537,3.29057948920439,-4.47028386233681));
#1127=CARTESIAN_POINT('',(36.3583871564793,3.12772920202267,-4.58570164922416));
#1128=CARTESIAN_POINT('',(36.4503790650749,3.0419766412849,-4.64317406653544));
#1129=CARTESIAN_POINT('',(36.6281804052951,2.86064113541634,-4.75707411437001));
#1130=CARTESIAN_POINT('',(36.7138800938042,2.76493305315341,-4.81347428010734));
#1131=CARTESIAN_POINT('',(36.8770160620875,2.56491197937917,-4.92296818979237));
#1132=CARTESIAN_POINT('',(36.954451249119,2.46059785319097,-4.97606149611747));
#1133=CARTESIAN_POINT('',(37.100127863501,2.24386878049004,-5.07747289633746));
#1134=CARTESIAN_POINT('',(37.1683863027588,2.13146943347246,-5.12579978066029));
#1135=CARTESIAN_POINT('',(37.29491910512,1.89890802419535,-5.21642520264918));
#1136=CARTESIAN_POINT('',(37.3531981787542,1.77874966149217,-5.25872658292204));
#1137=CARTESIAN_POINT('',(37.4439058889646,1.56622364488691,-5.32513054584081));
#1138=CARTESIAN_POINT('',(37.4789964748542,1.4755360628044,-5.35100662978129));
#1139=CARTESIAN_POINT('',(37.5430944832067,1.29096184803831,-5.39850728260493));
#1140=CARTESIAN_POINT('',(37.5721033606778,1.19707598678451,-5.42013286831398));
#1141=CARTESIAN_POINT('',(37.6236159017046,1.0068038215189,-5.45867560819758));
#1142=CARTESIAN_POINT('',(37.6461329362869,0.910423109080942,-5.47560243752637));
#1143=CARTESIAN_POINT('',(37.6844114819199,0.715624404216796,-5.50444899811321));
#1144=CARTESIAN_POINT('',(37.700175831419,0.617207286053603,-5.51637083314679));
#1145=CARTESIAN_POINT('',(37.7230526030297,0.432452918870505,-5.53369497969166));
#1146=CARTESIAN_POINT('',(37.7310480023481,0.346286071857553,-5.53976185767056));
#1147=CARTESIAN_POINT('',(37.7417225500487,0.173415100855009,-5.54786506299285));
#1148=CARTESIAN_POINT('',(37.7444005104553,0.0867108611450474,-5.5499004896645));
#1149=CARTESIAN_POINT('',(37.7444,0.,-5.54990000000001));
#1150=B_SPLINE_CURVE_WITH_KNOTS('',3,(#1008,#1009,#1010,#1011,#1012,#1013,#1014,#1015,#1016,
#1017,#1018,#1019,#1020,#1021,#1022,#1023,#1024,#1025,#1026,#1027,#1028,#1029,#1030,#1031,#1032,
#1033,#1034,#1035,#1036,#1037,#1038,#1039,#1040,#1041,#1042,#1043,#1044,#1045,#1046,#1047,#1048,
#1049,#1050,#1051,#1052,#1053,#1054,#1055,#1056,#1057,#1058,#1059,#1060,#1061,#1062,#1063,#1064,
#1065,#1066,#1067,#1068,#1069,#1070,#1071,#1072,#1073,#1074,#1075,#1076,#1077,#1078,#1079,#1080,
#1081,#1082,#1083,#1084,#1085,#1086,#1087,#1088,#1089,#1090,#1091,#1092,#1093,#1094,#1095,#1096,
#1097,#1098,#1099,#1100,#1101,#1102,#1103,#1104,#1105,#1106,#1107,#1108,#1109,#1110,#1111,#1112,
#1113,#1114,#1115,#1116,#1117,#1118,#1119,#1120,#1121,#1122,#1123,#1124,#1125,#1126,#1127,#1128,
#1129,#1130,#1131,#1132,#1133,#1134,#1135,#1136,#1137,#1138,#1139,#1140,#1141,#1142,#1143,#1144,
#1145,#1146,#1147,#1148,#1149),.UNSPECIFIED.,.T.,.F.,(4,2,2,2,2,2,2,2,2,2,2,2,2,2,2,2,2,2,2,2,2,
2,2,2,2,2,2,2,2,2,2,2,2,2,2,2,2,2,2,2,2,2,2,2,2,2,2,2,2,2,2,2,2,2,2,2,2,2,2,2,2,2,2,2,2,2,2,2,2,
2,4),(0.,0.307909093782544,0.615964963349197,0.924486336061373,1.23314414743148,
1.84608968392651,2.45893315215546,3.12888302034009,3.79984133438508,4.20549409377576,
4.61127134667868,5.01667578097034,5.42184749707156,5.94866107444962,6.21175949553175,
6.4747199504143,6.7403846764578,7.00603999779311,7.27175353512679,7.53746874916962,
8.00678580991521,8.47658235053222,8.86232249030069,9.24826914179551,9.63503095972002,
10.0217299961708,10.4195319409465,10.817488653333,11.6111347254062,12.2523588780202,
12.5731486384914,12.8937972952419,13.2167540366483,13.5395596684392,13.8623074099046,
14.1850259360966,14.4726847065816,14.7604340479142,15.3354443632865,15.9256524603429,
16.5159493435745,17.2032337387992,17.891918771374,18.3050679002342,18.7183646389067,
19.1308991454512,19.5431210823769,20.0506303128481,20.3040712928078,20.5573924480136,
20.8125962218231,21.0677912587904,21.3231577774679,21.5786570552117,21.8757972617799,
22.173153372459,22.7686074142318,23.1824806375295,23.5965024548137,24.0109105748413,
24.4252640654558,24.8456610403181,25.2661135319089,25.6857755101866,26.1052388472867,
26.4068178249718,26.7083245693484,27.0092058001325,27.3099604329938,27.5699574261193,
27.8300124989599),.UNSPECIFIED.);
#1151=CARTESIAN_POINT('',(37.7444,0.,-5.54990000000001));
#1152=VERTEX_POINT('',#1151);
#1153=EDGE_CURVE('E376',#1152,#1152,#1150,.T.);
#1154=ORIENTED_EDGE('',*,*,#1153,.T.);
#1155=EDGE_LOOP('',(#1154));
#1156=FACE_BOUND('',#1155,.T.);
#1157=ADVANCED_FACE('F360',(#993,#1004,#1007,#1156),#990,.F.);
#1158=CARTESIAN_POINT('',(52.9844,0.,0.));
#1159=DIRECTION('',(1.,0.,0.));
#1160=DIRECTION('',(0.,0.,-1.));
#1161=AXIS2_PLACEMENT_3D('',#1158,#1159,#1160);
#1162=CONICAL_SURFACE('',#1161,6.73100000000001,0.0523598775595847);
#1163=CARTESIAN_POINT('',(45.0595999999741,0.,0.));
#1164=DIRECTION('',(-1.,0.,0.));
#1165=DIRECTION('',(0.,0.,1.));
#1166=AXIS2_PLACEMENT_3D('',#1163,#1164,#1165);
#1167=CIRCLE('',#1166,6.31567883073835);
#1168=CARTESIAN_POINT('',(45.0595999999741,0.,6.31567883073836));
#1169=VERTEX_POINT('',#1168);
#1170=EDGE_CURVE('E644',#1169,#1169,#1167,.T.);
#1171=ORIENTED_EDGE('',*,*,#1170,.T.);
#1172=EDGE_LOOP('',(#1171));
#1173=FACE_BOUND('',#1172,.T.);
#1174=ORIENTED_EDGE('',*,*,#236,.F.);
#1175=EDGE_LOOP('',(#1174));
#1176=FACE_BOUND('',#1175,.T.);
#1177=ADVANCED_FACE('F354',(#1173,#1176),#1162,.F.);
#1178=CARTESIAN_POINT('',(45.059599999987,0.,-5.5499));
#1179=DIRECTION('',(1.,0.,0.));
#1180=DIRECTION('',(0.,0.,-1.));
#1181=AXIS2_PLACEMENT_3D('',#1178,#1179,#1180);
#1182=PLANE('',#1181);
#1183=ORIENTED_EDGE('',*,*,#1001,.T.);
#1184=EDGE_LOOP('',(#1183));
#1185=FACE_BOUND('',#1184,.T.);
#1186=ORIENTED_EDGE('',*,*,#1170,.F.);
#1187=EDGE_LOOP('',(#1186));
#1188=FACE_BOUND('',#1187,.T.);
#1189=ADVANCED_FACE('F348',(#1185,#1188),#1182,.T.);
#1190=CARTESIAN_POINT('',(33.528,0.,-6.34999999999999));
#1191=DIRECTION('',(0.,0.,1.));
#1192=DIRECTION('',(1.,0.,0.));
#1193=AXIS2_PLACEMENT_3D('',#1190,#1191,#1192);
#1194=CONICAL_SURFACE('',#1193,4.2164,1.02974425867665);
#1195=CARTESIAN_POINT('',(33.528,0.,-8.8834687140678));
#1196=VERTEX_POINT('',#1195);
#1197=VERTEX_LOOP('',#1196);
#1198=FACE_BOUND('',#1197,.T.);
#1199=CARTESIAN_POINT('',(33.528,0.,-6.34999999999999));
#1200=DIRECTION('',(0.,0.,1.));
#1201=DIRECTION('',(1.,0.,0.));
#1202=AXIS2_PLACEMENT_3D('',#1199,#1200,#1201);
#1203=CIRCLE('',#1202,4.2164);
#1204=CARTESIAN_POINT('',(37.7444,0.,-6.34999999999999));
#1205=VERTEX_POINT('',#1204);
#1206=EDGE_CURVE('E322',#1205,#1205,#1203,.T.);
#1207=ORIENTED_EDGE('',*,*,#1206,.T.);
#1208=EDGE_LOOP('',(#1207));
#1209=FACE_BOUND('',#1208,.T.);
#1210=ADVANCED_FACE('F229',(#1198,#1209),#1194,.F.);
#1211=ORIENTED_EDGE('',*,*,#1206,.F.);
#1212=EDGE_LOOP('',(#1211));
#1213=FACE_BOUND('',#1212,.T.);
#1214=ORIENTED_EDGE('',*,*,#1153,.F.);
#1215=EDGE_LOOP('',(#1214));
#1216=FACE_BOUND('',#1215,.T.);
#1217=ADVANCED_FACE('F347',(#1213,#1216),#51,.F.);
#1218=CLOSED_SHELL('',(#46,#212,#240,#268,#328,#373,#468,#480,#493,#513,#533,#573,#615,#646,
#677,#714,#738,#757,#783,#863,#901,#921,#933,#953,#965,#985,#1157,#1177,#1189,#1210,#1217));
#1219=MANIFOLD_SOLID_BREP('B2',#1218);
#1220=ADVANCED_BREP_SHAPE_REPRESENTATION('',(#18,#1219),#14);
#1221=SHAPE_DEFINITION_REPRESENTATION(#9,#1220);
ENDSEC;
END-ISO-10303-21;
